VERSION 5.7 ;
  NOWIREEXTENSIONATPIN ON ;
  DIVIDERCHAR "/" ;
  BUSBITCHARS "[]" ;
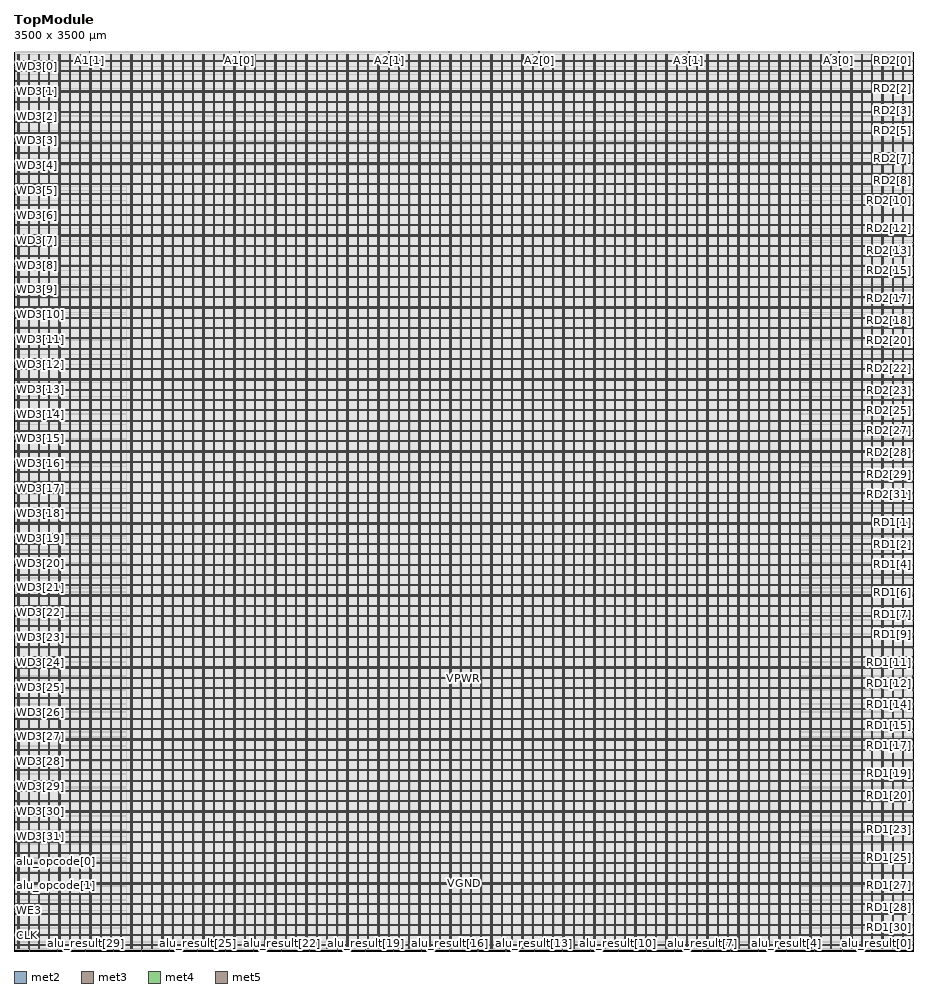
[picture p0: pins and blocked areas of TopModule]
MACRO TopModule
  CLASS BLOCK ;
  FOREIGN TopModule ;
  ORIGIN 0.000 0.000 ;
  SIZE 3500.000 BY 3500.000 ;
  PIN A1[0]
    DIRECTION INPUT ;
    USE SIGNAL ;
    ANTENNAGATEAREA 0.990000 ;
    PORT
      LAYER met2 ;
        RECT 875.010 3496.000 875.290 3500.000 ;
    END
  END A1[0]
  PIN A1[1]
    DIRECTION INPUT ;
    USE SIGNAL ;
    ANTENNAGATEAREA 0.990000 ;
    PORT
      LAYER met2 ;
        RECT 291.730 3496.000 292.010 3500.000 ;
    END
  END A1[1]
  PIN A2[0]
    DIRECTION INPUT ;
    USE SIGNAL ;
    ANTENNAGATEAREA 0.852000 ;
    PORT
      LAYER met2 ;
        RECT 2041.570 3496.000 2041.850 3500.000 ;
    END
  END A2[0]
  PIN A2[1]
    DIRECTION INPUT ;
    USE SIGNAL ;
    ANTENNAGATEAREA 0.495000 ;
    PORT
      LAYER met2 ;
        RECT 1458.290 3496.000 1458.570 3500.000 ;
    END
  END A2[1]
  PIN A3[0]
    DIRECTION INPUT ;
    USE SIGNAL ;
    ANTENNAGATEAREA 0.990000 ;
    PORT
      LAYER met2 ;
        RECT 3208.130 3496.000 3208.410 3500.000 ;
    END
  END A3[0]
  PIN A3[1]
    DIRECTION INPUT ;
    USE SIGNAL ;
    ANTENNAGATEAREA 0.990000 ;
    PORT
      LAYER met2 ;
        RECT 2624.850 3496.000 2625.130 3500.000 ;
    END
  END A3[1]
  PIN CLK
    DIRECTION INPUT ;
    USE SIGNAL ;
    ANTENNAGATEAREA 0.852000 ;
    ANTENNADIFFAREA 2.173500 ;
    PORT
      LAYER met3 ;
        RECT 0.000 59.880 4.000 60.480 ;
    END
  END CLK
  PIN RD1[0]
    DIRECTION OUTPUT ;
    USE SIGNAL ;
    ANTENNADIFFAREA 0.340600 ;
    PORT
      LAYER met3 ;
        RECT 3496.000 1721.800 3500.000 1722.400 ;
    END
  END RD1[0]
  PIN RD1[10]
    DIRECTION OUTPUT ;
    USE SIGNAL ;
    ANTENNADIFFAREA 0.340600 ;
    PORT
      LAYER met3 ;
        RECT 3496.000 1177.800 3500.000 1178.400 ;
    END
  END RD1[10]
  PIN RD1[11]
    DIRECTION OUTPUT ;
    USE SIGNAL ;
    ANTENNADIFFAREA 0.340600 ;
    PORT
      LAYER met3 ;
        RECT 3496.000 1123.400 3500.000 1124.000 ;
    END
  END RD1[11]
  PIN RD1[12]
    DIRECTION OUTPUT ;
    USE SIGNAL ;
    ANTENNADIFFAREA 0.340600 ;
    PORT
      LAYER met3 ;
        RECT 3496.000 1069.000 3500.000 1069.600 ;
    END
  END RD1[12]
  PIN RD1[13]
    DIRECTION OUTPUT ;
    USE SIGNAL ;
    ANTENNADIFFAREA 0.340600 ;
    PORT
      LAYER met3 ;
        RECT 3496.000 1014.600 3500.000 1015.200 ;
    END
  END RD1[13]
  PIN RD1[14]
    DIRECTION OUTPUT ;
    USE SIGNAL ;
    ANTENNADIFFAREA 0.340600 ;
    PORT
      LAYER met3 ;
        RECT 3496.000 960.200 3500.000 960.800 ;
    END
  END RD1[14]
  PIN RD1[15]
    DIRECTION OUTPUT ;
    USE SIGNAL ;
    ANTENNADIFFAREA 0.340600 ;
    PORT
      LAYER met3 ;
        RECT 3496.000 905.800 3500.000 906.400 ;
    END
  END RD1[15]
  PIN RD1[16]
    DIRECTION OUTPUT ;
    USE SIGNAL ;
    ANTENNADIFFAREA 0.340600 ;
    PORT
      LAYER met3 ;
        RECT 3496.000 851.400 3500.000 852.000 ;
    END
  END RD1[16]
  PIN RD1[17]
    DIRECTION OUTPUT ;
    USE SIGNAL ;
    ANTENNADIFFAREA 0.340600 ;
    PORT
      LAYER met3 ;
        RECT 3496.000 797.000 3500.000 797.600 ;
    END
  END RD1[17]
  PIN RD1[18]
    DIRECTION OUTPUT ;
    USE SIGNAL ;
    ANTENNADIFFAREA 0.340600 ;
    PORT
      LAYER met3 ;
        RECT 3496.000 742.600 3500.000 743.200 ;
    END
  END RD1[18]
  PIN RD1[19]
    DIRECTION OUTPUT ;
    USE SIGNAL ;
    ANTENNADIFFAREA 0.340600 ;
    PORT
      LAYER met3 ;
        RECT 3496.000 688.200 3500.000 688.800 ;
    END
  END RD1[19]
  PIN RD1[1]
    DIRECTION OUTPUT ;
    USE SIGNAL ;
    ANTENNADIFFAREA 0.340600 ;
    PORT
      LAYER met3 ;
        RECT 3496.000 1667.400 3500.000 1668.000 ;
    END
  END RD1[1]
  PIN RD1[20]
    DIRECTION OUTPUT ;
    USE SIGNAL ;
    ANTENNADIFFAREA 0.340600 ;
    PORT
      LAYER met3 ;
        RECT 3496.000 633.800 3500.000 634.400 ;
    END
  END RD1[20]
  PIN RD1[21]
    DIRECTION OUTPUT ;
    USE SIGNAL ;
    ANTENNADIFFAREA 0.340600 ;
    PORT
      LAYER met3 ;
        RECT 3496.000 579.400 3500.000 580.000 ;
    END
  END RD1[21]
  PIN RD1[22]
    DIRECTION OUTPUT ;
    USE SIGNAL ;
    ANTENNADIFFAREA 0.340600 ;
    PORT
      LAYER met3 ;
        RECT 3496.000 525.000 3500.000 525.600 ;
    END
  END RD1[22]
  PIN RD1[23]
    DIRECTION OUTPUT ;
    USE SIGNAL ;
    ANTENNADIFFAREA 0.340600 ;
    PORT
      LAYER met3 ;
        RECT 3496.000 470.600 3500.000 471.200 ;
    END
  END RD1[23]
  PIN RD1[24]
    DIRECTION OUTPUT ;
    USE SIGNAL ;
    ANTENNADIFFAREA 0.340600 ;
    PORT
      LAYER met3 ;
        RECT 3496.000 416.200 3500.000 416.800 ;
    END
  END RD1[24]
  PIN RD1[25]
    DIRECTION OUTPUT ;
    USE SIGNAL ;
    ANTENNADIFFAREA 0.340600 ;
    PORT
      LAYER met3 ;
        RECT 3496.000 361.800 3500.000 362.400 ;
    END
  END RD1[25]
  PIN RD1[26]
    DIRECTION OUTPUT ;
    USE SIGNAL ;
    ANTENNADIFFAREA 0.340600 ;
    PORT
      LAYER met3 ;
        RECT 3496.000 307.400 3500.000 308.000 ;
    END
  END RD1[26]
  PIN RD1[27]
    DIRECTION OUTPUT ;
    USE SIGNAL ;
    ANTENNADIFFAREA 0.340600 ;
    PORT
      LAYER met3 ;
        RECT 3496.000 253.000 3500.000 253.600 ;
    END
  END RD1[27]
  PIN RD1[28]
    DIRECTION OUTPUT ;
    USE SIGNAL ;
    ANTENNADIFFAREA 0.340600 ;
    PORT
      LAYER met3 ;
        RECT 3496.000 198.600 3500.000 199.200 ;
    END
  END RD1[28]
  PIN RD1[29]
    DIRECTION OUTPUT ;
    USE SIGNAL ;
    ANTENNADIFFAREA 0.340600 ;
    PORT
      LAYER met3 ;
        RECT 3496.000 144.200 3500.000 144.800 ;
    END
  END RD1[29]
  PIN RD1[2]
    DIRECTION OUTPUT ;
    USE SIGNAL ;
    ANTENNADIFFAREA 0.340600 ;
    PORT
      LAYER met3 ;
        RECT 3496.000 1613.000 3500.000 1613.600 ;
    END
  END RD1[2]
  PIN RD1[30]
    DIRECTION OUTPUT ;
    USE SIGNAL ;
    ANTENNADIFFAREA 0.340600 ;
    PORT
      LAYER met3 ;
        RECT 3496.000 89.800 3500.000 90.400 ;
    END
  END RD1[30]
  PIN RD1[31]
    DIRECTION OUTPUT ;
    USE SIGNAL ;
    ANTENNADIFFAREA 0.340600 ;
    PORT
      LAYER met3 ;
        RECT 3496.000 35.400 3500.000 36.000 ;
    END
  END RD1[31]
  PIN RD1[3]
    DIRECTION OUTPUT ;
    USE SIGNAL ;
    ANTENNADIFFAREA 0.340600 ;
    PORT
      LAYER met3 ;
        RECT 3496.000 1558.600 3500.000 1559.200 ;
    END
  END RD1[3]
  PIN RD1[4]
    DIRECTION OUTPUT ;
    USE SIGNAL ;
    ANTENNADIFFAREA 0.340600 ;
    PORT
      LAYER met3 ;
        RECT 3496.000 1504.200 3500.000 1504.800 ;
    END
  END RD1[4]
  PIN RD1[5]
    DIRECTION OUTPUT ;
    USE SIGNAL ;
    ANTENNADIFFAREA 0.340600 ;
    PORT
      LAYER met3 ;
        RECT 3496.000 1449.800 3500.000 1450.400 ;
    END
  END RD1[5]
  PIN RD1[6]
    DIRECTION OUTPUT ;
    USE SIGNAL ;
    ANTENNADIFFAREA 0.340600 ;
    PORT
      LAYER met3 ;
        RECT 3496.000 1395.400 3500.000 1396.000 ;
    END
  END RD1[6]
  PIN RD1[7]
    DIRECTION OUTPUT ;
    USE SIGNAL ;
    ANTENNADIFFAREA 0.340600 ;
    PORT
      LAYER met3 ;
        RECT 3496.000 1341.000 3500.000 1341.600 ;
    END
  END RD1[7]
  PIN RD1[8]
    DIRECTION OUTPUT ;
    USE SIGNAL ;
    ANTENNADIFFAREA 0.340600 ;
    PORT
      LAYER met3 ;
        RECT 3496.000 1286.600 3500.000 1287.200 ;
    END
  END RD1[8]
  PIN RD1[9]
    DIRECTION OUTPUT ;
    USE SIGNAL ;
    ANTENNADIFFAREA 0.340600 ;
    PORT
      LAYER met3 ;
        RECT 3496.000 1232.200 3500.000 1232.800 ;
    END
  END RD1[9]
  PIN RD2[0]
    DIRECTION OUTPUT ;
    USE SIGNAL ;
    ANTENNADIFFAREA 0.340600 ;
    PORT
      LAYER met3 ;
        RECT 3496.000 3462.600 3500.000 3463.200 ;
    END
  END RD2[0]
  PIN RD2[10]
    DIRECTION OUTPUT ;
    USE SIGNAL ;
    ANTENNADIFFAREA 0.340600 ;
    PORT
      LAYER met3 ;
        RECT 3496.000 2918.600 3500.000 2919.200 ;
    END
  END RD2[10]
  PIN RD2[11]
    DIRECTION OUTPUT ;
    USE SIGNAL ;
    ANTENNADIFFAREA 0.340600 ;
    PORT
      LAYER met3 ;
        RECT 3496.000 2864.200 3500.000 2864.800 ;
    END
  END RD2[11]
  PIN RD2[12]
    DIRECTION OUTPUT ;
    USE SIGNAL ;
    ANTENNADIFFAREA 0.340600 ;
    PORT
      LAYER met3 ;
        RECT 3496.000 2809.800 3500.000 2810.400 ;
    END
  END RD2[12]
  PIN RD2[13]
    DIRECTION OUTPUT ;
    USE SIGNAL ;
    ANTENNADIFFAREA 0.340600 ;
    PORT
      LAYER met3 ;
        RECT 3496.000 2755.400 3500.000 2756.000 ;
    END
  END RD2[13]
  PIN RD2[14]
    DIRECTION OUTPUT ;
    USE SIGNAL ;
    ANTENNADIFFAREA 0.340600 ;
    PORT
      LAYER met3 ;
        RECT 3496.000 2701.000 3500.000 2701.600 ;
    END
  END RD2[14]
  PIN RD2[15]
    DIRECTION OUTPUT ;
    USE SIGNAL ;
    ANTENNADIFFAREA 0.340600 ;
    PORT
      LAYER met3 ;
        RECT 3496.000 2646.600 3500.000 2647.200 ;
    END
  END RD2[15]
  PIN RD2[16]
    DIRECTION OUTPUT ;
    USE SIGNAL ;
    ANTENNADIFFAREA 0.340600 ;
    PORT
      LAYER met3 ;
        RECT 3496.000 2592.200 3500.000 2592.800 ;
    END
  END RD2[16]
  PIN RD2[17]
    DIRECTION OUTPUT ;
    USE SIGNAL ;
    ANTENNADIFFAREA 0.340600 ;
    PORT
      LAYER met3 ;
        RECT 3496.000 2537.800 3500.000 2538.400 ;
    END
  END RD2[17]
  PIN RD2[18]
    DIRECTION OUTPUT ;
    USE SIGNAL ;
    ANTENNADIFFAREA 0.340600 ;
    PORT
      LAYER met3 ;
        RECT 3496.000 2483.400 3500.000 2484.000 ;
    END
  END RD2[18]
  PIN RD2[19]
    DIRECTION OUTPUT ;
    USE SIGNAL ;
    ANTENNADIFFAREA 0.340600 ;
    PORT
      LAYER met3 ;
        RECT 3496.000 2429.000 3500.000 2429.600 ;
    END
  END RD2[19]
  PIN RD2[1]
    DIRECTION OUTPUT ;
    USE SIGNAL ;
    ANTENNADIFFAREA 0.340600 ;
    PORT
      LAYER met3 ;
        RECT 3496.000 3408.200 3500.000 3408.800 ;
    END
  END RD2[1]
  PIN RD2[20]
    DIRECTION OUTPUT ;
    USE SIGNAL ;
    ANTENNADIFFAREA 0.340600 ;
    PORT
      LAYER met3 ;
        RECT 3496.000 2374.600 3500.000 2375.200 ;
    END
  END RD2[20]
  PIN RD2[21]
    DIRECTION OUTPUT ;
    USE SIGNAL ;
    ANTENNADIFFAREA 0.340600 ;
    PORT
      LAYER met3 ;
        RECT 3496.000 2320.200 3500.000 2320.800 ;
    END
  END RD2[21]
  PIN RD2[22]
    DIRECTION OUTPUT ;
    USE SIGNAL ;
    ANTENNADIFFAREA 0.340600 ;
    PORT
      LAYER met3 ;
        RECT 3496.000 2265.800 3500.000 2266.400 ;
    END
  END RD2[22]
  PIN RD2[23]
    DIRECTION OUTPUT ;
    USE SIGNAL ;
    ANTENNADIFFAREA 0.340600 ;
    PORT
      LAYER met3 ;
        RECT 3496.000 2211.400 3500.000 2212.000 ;
    END
  END RD2[23]
  PIN RD2[24]
    DIRECTION OUTPUT ;
    USE SIGNAL ;
    ANTENNADIFFAREA 0.340600 ;
    PORT
      LAYER met3 ;
        RECT 3496.000 2157.000 3500.000 2157.600 ;
    END
  END RD2[24]
  PIN RD2[25]
    DIRECTION OUTPUT ;
    USE SIGNAL ;
    ANTENNADIFFAREA 0.340600 ;
    PORT
      LAYER met3 ;
        RECT 3496.000 2102.600 3500.000 2103.200 ;
    END
  END RD2[25]
  PIN RD2[26]
    DIRECTION OUTPUT ;
    USE SIGNAL ;
    ANTENNADIFFAREA 0.340600 ;
    PORT
      LAYER met3 ;
        RECT 3496.000 2048.200 3500.000 2048.800 ;
    END
  END RD2[26]
  PIN RD2[27]
    DIRECTION OUTPUT ;
    USE SIGNAL ;
    ANTENNADIFFAREA 0.340600 ;
    PORT
      LAYER met3 ;
        RECT 3496.000 1993.800 3500.000 1994.400 ;
    END
  END RD2[27]
  PIN RD2[28]
    DIRECTION OUTPUT ;
    USE SIGNAL ;
    ANTENNADIFFAREA 0.340600 ;
    PORT
      LAYER met3 ;
        RECT 3496.000 1939.400 3500.000 1940.000 ;
    END
  END RD2[28]
  PIN RD2[29]
    DIRECTION OUTPUT ;
    USE SIGNAL ;
    ANTENNADIFFAREA 0.340600 ;
    PORT
      LAYER met3 ;
        RECT 3496.000 1885.000 3500.000 1885.600 ;
    END
  END RD2[29]
  PIN RD2[2]
    DIRECTION OUTPUT ;
    USE SIGNAL ;
    ANTENNADIFFAREA 0.340600 ;
    PORT
      LAYER met3 ;
        RECT 3496.000 3353.800 3500.000 3354.400 ;
    END
  END RD2[2]
  PIN RD2[30]
    DIRECTION OUTPUT ;
    USE SIGNAL ;
    ANTENNADIFFAREA 0.340600 ;
    PORT
      LAYER met3 ;
        RECT 3496.000 1830.600 3500.000 1831.200 ;
    END
  END RD2[30]
  PIN RD2[31]
    DIRECTION OUTPUT ;
    USE SIGNAL ;
    ANTENNADIFFAREA 0.340600 ;
    PORT
      LAYER met3 ;
        RECT 3496.000 1776.200 3500.000 1776.800 ;
    END
  END RD2[31]
  PIN RD2[3]
    DIRECTION OUTPUT ;
    USE SIGNAL ;
    ANTENNADIFFAREA 0.340600 ;
    PORT
      LAYER met3 ;
        RECT 3496.000 3299.400 3500.000 3300.000 ;
    END
  END RD2[3]
  PIN RD2[4]
    DIRECTION OUTPUT ;
    USE SIGNAL ;
    ANTENNADIFFAREA 0.340600 ;
    PORT
      LAYER met3 ;
        RECT 3496.000 3245.000 3500.000 3245.600 ;
    END
  END RD2[4]
  PIN RD2[5]
    DIRECTION OUTPUT ;
    USE SIGNAL ;
    ANTENNADIFFAREA 0.340600 ;
    PORT
      LAYER met3 ;
        RECT 3496.000 3190.600 3500.000 3191.200 ;
    END
  END RD2[5]
  PIN RD2[6]
    DIRECTION OUTPUT ;
    USE SIGNAL ;
    ANTENNADIFFAREA 0.340600 ;
    PORT
      LAYER met3 ;
        RECT 3496.000 3136.200 3500.000 3136.800 ;
    END
  END RD2[6]
  PIN RD2[7]
    DIRECTION OUTPUT ;
    USE SIGNAL ;
    ANTENNADIFFAREA 0.340600 ;
    PORT
      LAYER met3 ;
        RECT 3496.000 3081.800 3500.000 3082.400 ;
    END
  END RD2[7]
  PIN RD2[8]
    DIRECTION OUTPUT ;
    USE SIGNAL ;
    ANTENNADIFFAREA 0.340600 ;
    PORT
      LAYER met3 ;
        RECT 3496.000 3027.400 3500.000 3028.000 ;
    END
  END RD2[8]
  PIN RD2[9]
    DIRECTION OUTPUT ;
    USE SIGNAL ;
    ANTENNADIFFAREA 0.340600 ;
    PORT
      LAYER met3 ;
        RECT 3496.000 2973.000 3500.000 2973.600 ;
    END
  END RD2[9]
  PIN VGND
    DIRECTION INOUT ;
    USE GROUND ;
    PORT
      LAYER met4 ;
        RECT 18.020 10.640 19.620 3487.280 ;
    END
    PORT
      LAYER met4 ;
        RECT 58.020 10.640 59.620 3487.280 ;
    END
    PORT
      LAYER met4 ;
        RECT 98.020 10.640 99.620 3487.280 ;
    END
    PORT
      LAYER met4 ;
        RECT 138.020 10.640 139.620 3487.280 ;
    END
    PORT
      LAYER met4 ;
        RECT 178.020 10.640 179.620 3487.280 ;
    END
    PORT
      LAYER met4 ;
        RECT 218.020 10.640 219.620 3487.280 ;
    END
    PORT
      LAYER met4 ;
        RECT 258.020 10.640 259.620 3487.280 ;
    END
    PORT
      LAYER met4 ;
        RECT 298.020 10.640 299.620 3487.280 ;
    END
    PORT
      LAYER met4 ;
        RECT 338.020 10.640 339.620 3487.280 ;
    END
    PORT
      LAYER met4 ;
        RECT 378.020 10.640 379.620 3487.280 ;
    END
    PORT
      LAYER met4 ;
        RECT 418.020 10.640 419.620 3487.280 ;
    END
    PORT
      LAYER met4 ;
        RECT 458.020 10.640 459.620 3487.280 ;
    END
    PORT
      LAYER met4 ;
        RECT 498.020 10.640 499.620 3487.280 ;
    END
    PORT
      LAYER met4 ;
        RECT 538.020 10.640 539.620 3487.280 ;
    END
    PORT
      LAYER met4 ;
        RECT 578.020 10.640 579.620 3487.280 ;
    END
    PORT
      LAYER met4 ;
        RECT 618.020 10.640 619.620 3487.280 ;
    END
    PORT
      LAYER met4 ;
        RECT 658.020 10.640 659.620 3487.280 ;
    END
    PORT
      LAYER met4 ;
        RECT 698.020 10.640 699.620 3487.280 ;
    END
    PORT
      LAYER met4 ;
        RECT 738.020 10.640 739.620 3487.280 ;
    END
    PORT
      LAYER met4 ;
        RECT 778.020 10.640 779.620 3487.280 ;
    END
    PORT
      LAYER met4 ;
        RECT 818.020 10.640 819.620 3487.280 ;
    END
    PORT
      LAYER met4 ;
        RECT 858.020 10.640 859.620 3487.280 ;
    END
    PORT
      LAYER met4 ;
        RECT 898.020 10.640 899.620 3487.280 ;
    END
    PORT
      LAYER met4 ;
        RECT 938.020 10.640 939.620 3487.280 ;
    END
    PORT
      LAYER met4 ;
        RECT 978.020 10.640 979.620 3487.280 ;
    END
    PORT
      LAYER met4 ;
        RECT 1018.020 10.640 1019.620 3487.280 ;
    END
    PORT
      LAYER met4 ;
        RECT 1058.020 10.640 1059.620 3487.280 ;
    END
    PORT
      LAYER met4 ;
        RECT 1098.020 10.640 1099.620 3487.280 ;
    END
    PORT
      LAYER met4 ;
        RECT 1138.020 10.640 1139.620 3487.280 ;
    END
    PORT
      LAYER met4 ;
        RECT 1178.020 10.640 1179.620 3487.280 ;
    END
    PORT
      LAYER met4 ;
        RECT 1218.020 10.640 1219.620 3487.280 ;
    END
    PORT
      LAYER met4 ;
        RECT 1258.020 10.640 1259.620 3487.280 ;
    END
    PORT
      LAYER met4 ;
        RECT 1298.020 10.640 1299.620 3487.280 ;
    END
    PORT
      LAYER met4 ;
        RECT 1338.020 10.640 1339.620 3487.280 ;
    END
    PORT
      LAYER met4 ;
        RECT 1378.020 10.640 1379.620 3487.280 ;
    END
    PORT
      LAYER met4 ;
        RECT 1418.020 10.640 1419.620 3487.280 ;
    END
    PORT
      LAYER met4 ;
        RECT 1458.020 10.640 1459.620 3487.280 ;
    END
    PORT
      LAYER met4 ;
        RECT 1498.020 10.640 1499.620 3487.280 ;
    END
    PORT
      LAYER met4 ;
        RECT 1538.020 10.640 1539.620 3487.280 ;
    END
    PORT
      LAYER met4 ;
        RECT 1578.020 10.640 1579.620 3487.280 ;
    END
    PORT
      LAYER met4 ;
        RECT 1618.020 10.640 1619.620 3487.280 ;
    END
    PORT
      LAYER met4 ;
        RECT 1658.020 10.640 1659.620 3487.280 ;
    END
    PORT
      LAYER met4 ;
        RECT 1698.020 10.640 1699.620 3487.280 ;
    END
    PORT
      LAYER met4 ;
        RECT 1738.020 10.640 1739.620 3487.280 ;
    END
    PORT
      LAYER met4 ;
        RECT 1778.020 10.640 1779.620 3487.280 ;
    END
    PORT
      LAYER met4 ;
        RECT 1818.020 10.640 1819.620 3487.280 ;
    END
    PORT
      LAYER met4 ;
        RECT 1858.020 10.640 1859.620 3487.280 ;
    END
    PORT
      LAYER met4 ;
        RECT 1898.020 10.640 1899.620 3487.280 ;
    END
    PORT
      LAYER met4 ;
        RECT 1938.020 10.640 1939.620 3487.280 ;
    END
    PORT
      LAYER met4 ;
        RECT 1978.020 10.640 1979.620 3487.280 ;
    END
    PORT
      LAYER met4 ;
        RECT 2018.020 10.640 2019.620 3487.280 ;
    END
    PORT
      LAYER met4 ;
        RECT 2058.020 10.640 2059.620 3487.280 ;
    END
    PORT
      LAYER met4 ;
        RECT 2098.020 10.640 2099.620 3487.280 ;
    END
    PORT
      LAYER met4 ;
        RECT 2138.020 10.640 2139.620 3487.280 ;
    END
    PORT
      LAYER met4 ;
        RECT 2178.020 10.640 2179.620 3487.280 ;
    END
    PORT
      LAYER met4 ;
        RECT 2218.020 10.640 2219.620 3487.280 ;
    END
    PORT
      LAYER met4 ;
        RECT 2258.020 10.640 2259.620 3487.280 ;
    END
    PORT
      LAYER met4 ;
        RECT 2298.020 10.640 2299.620 3487.280 ;
    END
    PORT
      LAYER met4 ;
        RECT 2338.020 10.640 2339.620 3487.280 ;
    END
    PORT
      LAYER met4 ;
        RECT 2378.020 10.640 2379.620 3487.280 ;
    END
    PORT
      LAYER met4 ;
        RECT 2418.020 10.640 2419.620 3487.280 ;
    END
    PORT
      LAYER met4 ;
        RECT 2458.020 10.640 2459.620 3487.280 ;
    END
    PORT
      LAYER met4 ;
        RECT 2498.020 10.640 2499.620 3487.280 ;
    END
    PORT
      LAYER met4 ;
        RECT 2538.020 10.640 2539.620 3487.280 ;
    END
    PORT
      LAYER met4 ;
        RECT 2578.020 10.640 2579.620 3487.280 ;
    END
    PORT
      LAYER met4 ;
        RECT 2618.020 10.640 2619.620 3487.280 ;
    END
    PORT
      LAYER met4 ;
        RECT 2658.020 10.640 2659.620 3487.280 ;
    END
    PORT
      LAYER met4 ;
        RECT 2698.020 10.640 2699.620 3487.280 ;
    END
    PORT
      LAYER met4 ;
        RECT 2738.020 10.640 2739.620 3487.280 ;
    END
    PORT
      LAYER met4 ;
        RECT 2778.020 10.640 2779.620 3487.280 ;
    END
    PORT
      LAYER met4 ;
        RECT 2818.020 10.640 2819.620 3487.280 ;
    END
    PORT
      LAYER met4 ;
        RECT 2858.020 10.640 2859.620 3487.280 ;
    END
    PORT
      LAYER met4 ;
        RECT 2898.020 10.640 2899.620 3487.280 ;
    END
    PORT
      LAYER met4 ;
        RECT 2938.020 10.640 2939.620 3487.280 ;
    END
    PORT
      LAYER met4 ;
        RECT 2978.020 10.640 2979.620 3487.280 ;
    END
    PORT
      LAYER met4 ;
        RECT 3018.020 10.640 3019.620 3487.280 ;
    END
    PORT
      LAYER met4 ;
        RECT 3058.020 10.640 3059.620 3487.280 ;
    END
    PORT
      LAYER met4 ;
        RECT 3098.020 10.640 3099.620 3487.280 ;
    END
    PORT
      LAYER met4 ;
        RECT 3138.020 10.640 3139.620 3487.280 ;
    END
    PORT
      LAYER met4 ;
        RECT 3178.020 10.640 3179.620 3487.280 ;
    END
    PORT
      LAYER met4 ;
        RECT 3218.020 10.640 3219.620 3487.280 ;
    END
    PORT
      LAYER met4 ;
        RECT 3258.020 10.640 3259.620 3487.280 ;
    END
    PORT
      LAYER met4 ;
        RECT 3298.020 10.640 3299.620 3487.280 ;
    END
    PORT
      LAYER met4 ;
        RECT 3338.020 10.640 3339.620 3487.280 ;
    END
    PORT
      LAYER met4 ;
        RECT 3378.020 10.640 3379.620 3487.280 ;
    END
    PORT
      LAYER met4 ;
        RECT 3418.020 10.640 3419.620 3487.280 ;
    END
    PORT
      LAYER met4 ;
        RECT 3458.020 10.640 3459.620 3487.280 ;
    END
    PORT
      LAYER met5 ;
        RECT 5.280 23.380 3494.400 24.980 ;
    END
    PORT
      LAYER met5 ;
        RECT 5.280 63.380 3494.400 64.980 ;
    END
    PORT
      LAYER met5 ;
        RECT 5.280 103.380 3494.400 104.980 ;
    END
    PORT
      LAYER met5 ;
        RECT 5.280 143.380 3494.400 144.980 ;
    END
    PORT
      LAYER met5 ;
        RECT 5.280 183.380 3494.400 184.980 ;
    END
    PORT
      LAYER met5 ;
        RECT 5.280 223.380 3494.400 224.980 ;
    END
    PORT
      LAYER met5 ;
        RECT 5.280 263.380 3494.400 264.980 ;
    END
    PORT
      LAYER met5 ;
        RECT 5.280 303.380 3494.400 304.980 ;
    END
    PORT
      LAYER met5 ;
        RECT 5.280 343.380 3494.400 344.980 ;
    END
    PORT
      LAYER met5 ;
        RECT 5.280 383.380 3494.400 384.980 ;
    END
    PORT
      LAYER met5 ;
        RECT 5.280 423.380 3494.400 424.980 ;
    END
    PORT
      LAYER met5 ;
        RECT 5.280 463.380 3494.400 464.980 ;
    END
    PORT
      LAYER met5 ;
        RECT 5.280 503.380 3494.400 504.980 ;
    END
    PORT
      LAYER met5 ;
        RECT 5.280 543.380 3494.400 544.980 ;
    END
    PORT
      LAYER met5 ;
        RECT 5.280 583.380 3494.400 584.980 ;
    END
    PORT
      LAYER met5 ;
        RECT 5.280 623.380 3494.400 624.980 ;
    END
    PORT
      LAYER met5 ;
        RECT 5.280 663.380 3494.400 664.980 ;
    END
    PORT
      LAYER met5 ;
        RECT 5.280 703.380 3494.400 704.980 ;
    END
    PORT
      LAYER met5 ;
        RECT 5.280 743.380 3494.400 744.980 ;
    END
    PORT
      LAYER met5 ;
        RECT 5.280 783.380 3494.400 784.980 ;
    END
    PORT
      LAYER met5 ;
        RECT 5.280 823.380 3494.400 824.980 ;
    END
    PORT
      LAYER met5 ;
        RECT 5.280 863.380 3494.400 864.980 ;
    END
    PORT
      LAYER met5 ;
        RECT 5.280 903.380 3494.400 904.980 ;
    END
    PORT
      LAYER met5 ;
        RECT 5.280 943.380 3494.400 944.980 ;
    END
    PORT
      LAYER met5 ;
        RECT 5.280 983.380 3494.400 984.980 ;
    END
    PORT
      LAYER met5 ;
        RECT 5.280 1023.380 3494.400 1024.980 ;
    END
    PORT
      LAYER met5 ;
        RECT 5.280 1063.380 3494.400 1064.980 ;
    END
    PORT
      LAYER met5 ;
        RECT 5.280 1103.380 3494.400 1104.980 ;
    END
    PORT
      LAYER met5 ;
        RECT 5.280 1143.380 3494.400 1144.980 ;
    END
    PORT
      LAYER met5 ;
        RECT 5.280 1183.380 3494.400 1184.980 ;
    END
    PORT
      LAYER met5 ;
        RECT 5.280 1223.380 3494.400 1224.980 ;
    END
    PORT
      LAYER met5 ;
        RECT 5.280 1263.380 3494.400 1264.980 ;
    END
    PORT
      LAYER met5 ;
        RECT 5.280 1303.380 3494.400 1304.980 ;
    END
    PORT
      LAYER met5 ;
        RECT 5.280 1343.380 3494.400 1344.980 ;
    END
    PORT
      LAYER met5 ;
        RECT 5.280 1383.380 3494.400 1384.980 ;
    END
    PORT
      LAYER met5 ;
        RECT 5.280 1423.380 3494.400 1424.980 ;
    END
    PORT
      LAYER met5 ;
        RECT 5.280 1463.380 3494.400 1464.980 ;
    END
    PORT
      LAYER met5 ;
        RECT 5.280 1503.380 3494.400 1504.980 ;
    END
    PORT
      LAYER met5 ;
        RECT 5.280 1543.380 3494.400 1544.980 ;
    END
    PORT
      LAYER met5 ;
        RECT 5.280 1583.380 3494.400 1584.980 ;
    END
    PORT
      LAYER met5 ;
        RECT 5.280 1623.380 3494.400 1624.980 ;
    END
    PORT
      LAYER met5 ;
        RECT 5.280 1663.380 3494.400 1664.980 ;
    END
    PORT
      LAYER met5 ;
        RECT 5.280 1703.380 3494.400 1704.980 ;
    END
    PORT
      LAYER met5 ;
        RECT 5.280 1743.380 3494.400 1744.980 ;
    END
    PORT
      LAYER met5 ;
        RECT 5.280 1783.380 3494.400 1784.980 ;
    END
    PORT
      LAYER met5 ;
        RECT 5.280 1823.380 3494.400 1824.980 ;
    END
    PORT
      LAYER met5 ;
        RECT 5.280 1863.380 3494.400 1864.980 ;
    END
    PORT
      LAYER met5 ;
        RECT 5.280 1903.380 3494.400 1904.980 ;
    END
    PORT
      LAYER met5 ;
        RECT 5.280 1943.380 3494.400 1944.980 ;
    END
    PORT
      LAYER met5 ;
        RECT 5.280 1983.380 3494.400 1984.980 ;
    END
    PORT
      LAYER met5 ;
        RECT 5.280 2023.380 3494.400 2024.980 ;
    END
    PORT
      LAYER met5 ;
        RECT 5.280 2063.380 3494.400 2064.980 ;
    END
    PORT
      LAYER met5 ;
        RECT 5.280 2103.380 3494.400 2104.980 ;
    END
    PORT
      LAYER met5 ;
        RECT 5.280 2143.380 3494.400 2144.980 ;
    END
    PORT
      LAYER met5 ;
        RECT 5.280 2183.380 3494.400 2184.980 ;
    END
    PORT
      LAYER met5 ;
        RECT 5.280 2223.380 3494.400 2224.980 ;
    END
    PORT
      LAYER met5 ;
        RECT 5.280 2263.380 3494.400 2264.980 ;
    END
    PORT
      LAYER met5 ;
        RECT 5.280 2303.380 3494.400 2304.980 ;
    END
    PORT
      LAYER met5 ;
        RECT 5.280 2343.380 3494.400 2344.980 ;
    END
    PORT
      LAYER met5 ;
        RECT 5.280 2383.380 3494.400 2384.980 ;
    END
    PORT
      LAYER met5 ;
        RECT 5.280 2423.380 3494.400 2424.980 ;
    END
    PORT
      LAYER met5 ;
        RECT 5.280 2463.380 3494.400 2464.980 ;
    END
    PORT
      LAYER met5 ;
        RECT 5.280 2503.380 3494.400 2504.980 ;
    END
    PORT
      LAYER met5 ;
        RECT 5.280 2543.380 3494.400 2544.980 ;
    END
    PORT
      LAYER met5 ;
        RECT 5.280 2583.380 3494.400 2584.980 ;
    END
    PORT
      LAYER met5 ;
        RECT 5.280 2623.380 3494.400 2624.980 ;
    END
    PORT
      LAYER met5 ;
        RECT 5.280 2663.380 3494.400 2664.980 ;
    END
    PORT
      LAYER met5 ;
        RECT 5.280 2703.380 3494.400 2704.980 ;
    END
    PORT
      LAYER met5 ;
        RECT 5.280 2743.380 3494.400 2744.980 ;
    END
    PORT
      LAYER met5 ;
        RECT 5.280 2783.380 3494.400 2784.980 ;
    END
    PORT
      LAYER met5 ;
        RECT 5.280 2823.380 3494.400 2824.980 ;
    END
    PORT
      LAYER met5 ;
        RECT 5.280 2863.380 3494.400 2864.980 ;
    END
    PORT
      LAYER met5 ;
        RECT 5.280 2903.380 3494.400 2904.980 ;
    END
    PORT
      LAYER met5 ;
        RECT 5.280 2943.380 3494.400 2944.980 ;
    END
    PORT
      LAYER met5 ;
        RECT 5.280 2983.380 3494.400 2984.980 ;
    END
    PORT
      LAYER met5 ;
        RECT 5.280 3023.380 3494.400 3024.980 ;
    END
    PORT
      LAYER met5 ;
        RECT 5.280 3063.380 3494.400 3064.980 ;
    END
    PORT
      LAYER met5 ;
        RECT 5.280 3103.380 3494.400 3104.980 ;
    END
    PORT
      LAYER met5 ;
        RECT 5.280 3143.380 3494.400 3144.980 ;
    END
    PORT
      LAYER met5 ;
        RECT 5.280 3183.380 3494.400 3184.980 ;
    END
    PORT
      LAYER met5 ;
        RECT 5.280 3223.380 3494.400 3224.980 ;
    END
    PORT
      LAYER met5 ;
        RECT 5.280 3263.380 3494.400 3264.980 ;
    END
    PORT
      LAYER met5 ;
        RECT 5.280 3303.380 3494.400 3304.980 ;
    END
    PORT
      LAYER met5 ;
        RECT 5.280 3343.380 3494.400 3344.980 ;
    END
    PORT
      LAYER met5 ;
        RECT 5.280 3383.380 3494.400 3384.980 ;
    END
    PORT
      LAYER met5 ;
        RECT 5.280 3423.380 3494.400 3424.980 ;
    END
    PORT
      LAYER met5 ;
        RECT 5.280 3463.380 3494.400 3464.980 ;
    END
  END VGND
  PIN VPWR
    DIRECTION INOUT ;
    USE POWER ;
    PORT
      LAYER met4 ;
        RECT 14.720 10.640 16.320 3487.280 ;
    END
    PORT
      LAYER met4 ;
        RECT 54.720 10.640 56.320 3487.280 ;
    END
    PORT
      LAYER met4 ;
        RECT 94.720 10.640 96.320 3487.280 ;
    END
    PORT
      LAYER met4 ;
        RECT 134.720 10.640 136.320 3487.280 ;
    END
    PORT
      LAYER met4 ;
        RECT 174.720 10.640 176.320 3487.280 ;
    END
    PORT
      LAYER met4 ;
        RECT 214.720 10.640 216.320 3487.280 ;
    END
    PORT
      LAYER met4 ;
        RECT 254.720 10.640 256.320 3487.280 ;
    END
    PORT
      LAYER met4 ;
        RECT 294.720 10.640 296.320 3487.280 ;
    END
    PORT
      LAYER met4 ;
        RECT 334.720 10.640 336.320 3487.280 ;
    END
    PORT
      LAYER met4 ;
        RECT 374.720 10.640 376.320 3487.280 ;
    END
    PORT
      LAYER met4 ;
        RECT 414.720 10.640 416.320 3487.280 ;
    END
    PORT
      LAYER met4 ;
        RECT 454.720 10.640 456.320 3487.280 ;
    END
    PORT
      LAYER met4 ;
        RECT 494.720 10.640 496.320 3487.280 ;
    END
    PORT
      LAYER met4 ;
        RECT 534.720 10.640 536.320 3487.280 ;
    END
    PORT
      LAYER met4 ;
        RECT 574.720 10.640 576.320 3487.280 ;
    END
    PORT
      LAYER met4 ;
        RECT 614.720 10.640 616.320 3487.280 ;
    END
    PORT
      LAYER met4 ;
        RECT 654.720 10.640 656.320 3487.280 ;
    END
    PORT
      LAYER met4 ;
        RECT 694.720 10.640 696.320 3487.280 ;
    END
    PORT
      LAYER met4 ;
        RECT 734.720 10.640 736.320 3487.280 ;
    END
    PORT
      LAYER met4 ;
        RECT 774.720 10.640 776.320 3487.280 ;
    END
    PORT
      LAYER met4 ;
        RECT 814.720 10.640 816.320 3487.280 ;
    END
    PORT
      LAYER met4 ;
        RECT 854.720 10.640 856.320 3487.280 ;
    END
    PORT
      LAYER met4 ;
        RECT 894.720 10.640 896.320 3487.280 ;
    END
    PORT
      LAYER met4 ;
        RECT 934.720 10.640 936.320 3487.280 ;
    END
    PORT
      LAYER met4 ;
        RECT 974.720 10.640 976.320 3487.280 ;
    END
    PORT
      LAYER met4 ;
        RECT 1014.720 10.640 1016.320 3487.280 ;
    END
    PORT
      LAYER met4 ;
        RECT 1054.720 10.640 1056.320 3487.280 ;
    END
    PORT
      LAYER met4 ;
        RECT 1094.720 10.640 1096.320 3487.280 ;
    END
    PORT
      LAYER met4 ;
        RECT 1134.720 10.640 1136.320 3487.280 ;
    END
    PORT
      LAYER met4 ;
        RECT 1174.720 10.640 1176.320 3487.280 ;
    END
    PORT
      LAYER met4 ;
        RECT 1214.720 10.640 1216.320 3487.280 ;
    END
    PORT
      LAYER met4 ;
        RECT 1254.720 10.640 1256.320 3487.280 ;
    END
    PORT
      LAYER met4 ;
        RECT 1294.720 10.640 1296.320 3487.280 ;
    END
    PORT
      LAYER met4 ;
        RECT 1334.720 10.640 1336.320 3487.280 ;
    END
    PORT
      LAYER met4 ;
        RECT 1374.720 10.640 1376.320 3487.280 ;
    END
    PORT
      LAYER met4 ;
        RECT 1414.720 10.640 1416.320 3487.280 ;
    END
    PORT
      LAYER met4 ;
        RECT 1454.720 10.640 1456.320 3487.280 ;
    END
    PORT
      LAYER met4 ;
        RECT 1494.720 10.640 1496.320 3487.280 ;
    END
    PORT
      LAYER met4 ;
        RECT 1534.720 10.640 1536.320 3487.280 ;
    END
    PORT
      LAYER met4 ;
        RECT 1574.720 10.640 1576.320 3487.280 ;
    END
    PORT
      LAYER met4 ;
        RECT 1614.720 10.640 1616.320 3487.280 ;
    END
    PORT
      LAYER met4 ;
        RECT 1654.720 10.640 1656.320 3487.280 ;
    END
    PORT
      LAYER met4 ;
        RECT 1694.720 10.640 1696.320 3487.280 ;
    END
    PORT
      LAYER met4 ;
        RECT 1734.720 10.640 1736.320 3487.280 ;
    END
    PORT
      LAYER met4 ;
        RECT 1774.720 10.640 1776.320 3487.280 ;
    END
    PORT
      LAYER met4 ;
        RECT 1814.720 10.640 1816.320 3487.280 ;
    END
    PORT
      LAYER met4 ;
        RECT 1854.720 10.640 1856.320 3487.280 ;
    END
    PORT
      LAYER met4 ;
        RECT 1894.720 10.640 1896.320 3487.280 ;
    END
    PORT
      LAYER met4 ;
        RECT 1934.720 10.640 1936.320 3487.280 ;
    END
    PORT
      LAYER met4 ;
        RECT 1974.720 10.640 1976.320 3487.280 ;
    END
    PORT
      LAYER met4 ;
        RECT 2014.720 10.640 2016.320 3487.280 ;
    END
    PORT
      LAYER met4 ;
        RECT 2054.720 10.640 2056.320 3487.280 ;
    END
    PORT
      LAYER met4 ;
        RECT 2094.720 10.640 2096.320 3487.280 ;
    END
    PORT
      LAYER met4 ;
        RECT 2134.720 10.640 2136.320 3487.280 ;
    END
    PORT
      LAYER met4 ;
        RECT 2174.720 10.640 2176.320 3487.280 ;
    END
    PORT
      LAYER met4 ;
        RECT 2214.720 10.640 2216.320 3487.280 ;
    END
    PORT
      LAYER met4 ;
        RECT 2254.720 10.640 2256.320 3487.280 ;
    END
    PORT
      LAYER met4 ;
        RECT 2294.720 10.640 2296.320 3487.280 ;
    END
    PORT
      LAYER met4 ;
        RECT 2334.720 10.640 2336.320 3487.280 ;
    END
    PORT
      LAYER met4 ;
        RECT 2374.720 10.640 2376.320 3487.280 ;
    END
    PORT
      LAYER met4 ;
        RECT 2414.720 10.640 2416.320 3487.280 ;
    END
    PORT
      LAYER met4 ;
        RECT 2454.720 10.640 2456.320 3487.280 ;
    END
    PORT
      LAYER met4 ;
        RECT 2494.720 10.640 2496.320 3487.280 ;
    END
    PORT
      LAYER met4 ;
        RECT 2534.720 10.640 2536.320 3487.280 ;
    END
    PORT
      LAYER met4 ;
        RECT 2574.720 10.640 2576.320 3487.280 ;
    END
    PORT
      LAYER met4 ;
        RECT 2614.720 10.640 2616.320 3487.280 ;
    END
    PORT
      LAYER met4 ;
        RECT 2654.720 10.640 2656.320 3487.280 ;
    END
    PORT
      LAYER met4 ;
        RECT 2694.720 10.640 2696.320 3487.280 ;
    END
    PORT
      LAYER met4 ;
        RECT 2734.720 10.640 2736.320 3487.280 ;
    END
    PORT
      LAYER met4 ;
        RECT 2774.720 10.640 2776.320 3487.280 ;
    END
    PORT
      LAYER met4 ;
        RECT 2814.720 10.640 2816.320 3487.280 ;
    END
    PORT
      LAYER met4 ;
        RECT 2854.720 10.640 2856.320 3487.280 ;
    END
    PORT
      LAYER met4 ;
        RECT 2894.720 10.640 2896.320 3487.280 ;
    END
    PORT
      LAYER met4 ;
        RECT 2934.720 10.640 2936.320 3487.280 ;
    END
    PORT
      LAYER met4 ;
        RECT 2974.720 10.640 2976.320 3487.280 ;
    END
    PORT
      LAYER met4 ;
        RECT 3014.720 10.640 3016.320 3487.280 ;
    END
    PORT
      LAYER met4 ;
        RECT 3054.720 10.640 3056.320 3487.280 ;
    END
    PORT
      LAYER met4 ;
        RECT 3094.720 10.640 3096.320 3487.280 ;
    END
    PORT
      LAYER met4 ;
        RECT 3134.720 10.640 3136.320 3487.280 ;
    END
    PORT
      LAYER met4 ;
        RECT 3174.720 10.640 3176.320 3487.280 ;
    END
    PORT
      LAYER met4 ;
        RECT 3214.720 10.640 3216.320 3487.280 ;
    END
    PORT
      LAYER met4 ;
        RECT 3254.720 10.640 3256.320 3487.280 ;
    END
    PORT
      LAYER met4 ;
        RECT 3294.720 10.640 3296.320 3487.280 ;
    END
    PORT
      LAYER met4 ;
        RECT 3334.720 10.640 3336.320 3487.280 ;
    END
    PORT
      LAYER met4 ;
        RECT 3374.720 10.640 3376.320 3487.280 ;
    END
    PORT
      LAYER met4 ;
        RECT 3414.720 10.640 3416.320 3487.280 ;
    END
    PORT
      LAYER met4 ;
        RECT 3454.720 10.640 3456.320 3487.280 ;
    END
    PORT
      LAYER met5 ;
        RECT 5.280 20.080 3494.400 21.680 ;
    END
    PORT
      LAYER met5 ;
        RECT 5.280 60.080 3494.400 61.680 ;
    END
    PORT
      LAYER met5 ;
        RECT 5.280 100.080 3494.400 101.680 ;
    END
    PORT
      LAYER met5 ;
        RECT 5.280 140.080 3494.400 141.680 ;
    END
    PORT
      LAYER met5 ;
        RECT 5.280 180.080 3494.400 181.680 ;
    END
    PORT
      LAYER met5 ;
        RECT 5.280 220.080 3494.400 221.680 ;
    END
    PORT
      LAYER met5 ;
        RECT 5.280 260.080 3494.400 261.680 ;
    END
    PORT
      LAYER met5 ;
        RECT 5.280 300.080 3494.400 301.680 ;
    END
    PORT
      LAYER met5 ;
        RECT 5.280 340.080 3494.400 341.680 ;
    END
    PORT
      LAYER met5 ;
        RECT 5.280 380.080 3494.400 381.680 ;
    END
    PORT
      LAYER met5 ;
        RECT 5.280 420.080 3494.400 421.680 ;
    END
    PORT
      LAYER met5 ;
        RECT 5.280 460.080 3494.400 461.680 ;
    END
    PORT
      LAYER met5 ;
        RECT 5.280 500.080 3494.400 501.680 ;
    END
    PORT
      LAYER met5 ;
        RECT 5.280 540.080 3494.400 541.680 ;
    END
    PORT
      LAYER met5 ;
        RECT 5.280 580.080 3494.400 581.680 ;
    END
    PORT
      LAYER met5 ;
        RECT 5.280 620.080 3494.400 621.680 ;
    END
    PORT
      LAYER met5 ;
        RECT 5.280 660.080 3494.400 661.680 ;
    END
    PORT
      LAYER met5 ;
        RECT 5.280 700.080 3494.400 701.680 ;
    END
    PORT
      LAYER met5 ;
        RECT 5.280 740.080 3494.400 741.680 ;
    END
    PORT
      LAYER met5 ;
        RECT 5.280 780.080 3494.400 781.680 ;
    END
    PORT
      LAYER met5 ;
        RECT 5.280 820.080 3494.400 821.680 ;
    END
    PORT
      LAYER met5 ;
        RECT 5.280 860.080 3494.400 861.680 ;
    END
    PORT
      LAYER met5 ;
        RECT 5.280 900.080 3494.400 901.680 ;
    END
    PORT
      LAYER met5 ;
        RECT 5.280 940.080 3494.400 941.680 ;
    END
    PORT
      LAYER met5 ;
        RECT 5.280 980.080 3494.400 981.680 ;
    END
    PORT
      LAYER met5 ;
        RECT 5.280 1020.080 3494.400 1021.680 ;
    END
    PORT
      LAYER met5 ;
        RECT 5.280 1060.080 3494.400 1061.680 ;
    END
    PORT
      LAYER met5 ;
        RECT 5.280 1100.080 3494.400 1101.680 ;
    END
    PORT
      LAYER met5 ;
        RECT 5.280 1140.080 3494.400 1141.680 ;
    END
    PORT
      LAYER met5 ;
        RECT 5.280 1180.080 3494.400 1181.680 ;
    END
    PORT
      LAYER met5 ;
        RECT 5.280 1220.080 3494.400 1221.680 ;
    END
    PORT
      LAYER met5 ;
        RECT 5.280 1260.080 3494.400 1261.680 ;
    END
    PORT
      LAYER met5 ;
        RECT 5.280 1300.080 3494.400 1301.680 ;
    END
    PORT
      LAYER met5 ;
        RECT 5.280 1340.080 3494.400 1341.680 ;
    END
    PORT
      LAYER met5 ;
        RECT 5.280 1380.080 3494.400 1381.680 ;
    END
    PORT
      LAYER met5 ;
        RECT 5.280 1420.080 3494.400 1421.680 ;
    END
    PORT
      LAYER met5 ;
        RECT 5.280 1460.080 3494.400 1461.680 ;
    END
    PORT
      LAYER met5 ;
        RECT 5.280 1500.080 3494.400 1501.680 ;
    END
    PORT
      LAYER met5 ;
        RECT 5.280 1540.080 3494.400 1541.680 ;
    END
    PORT
      LAYER met5 ;
        RECT 5.280 1580.080 3494.400 1581.680 ;
    END
    PORT
      LAYER met5 ;
        RECT 5.280 1620.080 3494.400 1621.680 ;
    END
    PORT
      LAYER met5 ;
        RECT 5.280 1660.080 3494.400 1661.680 ;
    END
    PORT
      LAYER met5 ;
        RECT 5.280 1700.080 3494.400 1701.680 ;
    END
    PORT
      LAYER met5 ;
        RECT 5.280 1740.080 3494.400 1741.680 ;
    END
    PORT
      LAYER met5 ;
        RECT 5.280 1780.080 3494.400 1781.680 ;
    END
    PORT
      LAYER met5 ;
        RECT 5.280 1820.080 3494.400 1821.680 ;
    END
    PORT
      LAYER met5 ;
        RECT 5.280 1860.080 3494.400 1861.680 ;
    END
    PORT
      LAYER met5 ;
        RECT 5.280 1900.080 3494.400 1901.680 ;
    END
    PORT
      LAYER met5 ;
        RECT 5.280 1940.080 3494.400 1941.680 ;
    END
    PORT
      LAYER met5 ;
        RECT 5.280 1980.080 3494.400 1981.680 ;
    END
    PORT
      LAYER met5 ;
        RECT 5.280 2020.080 3494.400 2021.680 ;
    END
    PORT
      LAYER met5 ;
        RECT 5.280 2060.080 3494.400 2061.680 ;
    END
    PORT
      LAYER met5 ;
        RECT 5.280 2100.080 3494.400 2101.680 ;
    END
    PORT
      LAYER met5 ;
        RECT 5.280 2140.080 3494.400 2141.680 ;
    END
    PORT
      LAYER met5 ;
        RECT 5.280 2180.080 3494.400 2181.680 ;
    END
    PORT
      LAYER met5 ;
        RECT 5.280 2220.080 3494.400 2221.680 ;
    END
    PORT
      LAYER met5 ;
        RECT 5.280 2260.080 3494.400 2261.680 ;
    END
    PORT
      LAYER met5 ;
        RECT 5.280 2300.080 3494.400 2301.680 ;
    END
    PORT
      LAYER met5 ;
        RECT 5.280 2340.080 3494.400 2341.680 ;
    END
    PORT
      LAYER met5 ;
        RECT 5.280 2380.080 3494.400 2381.680 ;
    END
    PORT
      LAYER met5 ;
        RECT 5.280 2420.080 3494.400 2421.680 ;
    END
    PORT
      LAYER met5 ;
        RECT 5.280 2460.080 3494.400 2461.680 ;
    END
    PORT
      LAYER met5 ;
        RECT 5.280 2500.080 3494.400 2501.680 ;
    END
    PORT
      LAYER met5 ;
        RECT 5.280 2540.080 3494.400 2541.680 ;
    END
    PORT
      LAYER met5 ;
        RECT 5.280 2580.080 3494.400 2581.680 ;
    END
    PORT
      LAYER met5 ;
        RECT 5.280 2620.080 3494.400 2621.680 ;
    END
    PORT
      LAYER met5 ;
        RECT 5.280 2660.080 3494.400 2661.680 ;
    END
    PORT
      LAYER met5 ;
        RECT 5.280 2700.080 3494.400 2701.680 ;
    END
    PORT
      LAYER met5 ;
        RECT 5.280 2740.080 3494.400 2741.680 ;
    END
    PORT
      LAYER met5 ;
        RECT 5.280 2780.080 3494.400 2781.680 ;
    END
    PORT
      LAYER met5 ;
        RECT 5.280 2820.080 3494.400 2821.680 ;
    END
    PORT
      LAYER met5 ;
        RECT 5.280 2860.080 3494.400 2861.680 ;
    END
    PORT
      LAYER met5 ;
        RECT 5.280 2900.080 3494.400 2901.680 ;
    END
    PORT
      LAYER met5 ;
        RECT 5.280 2940.080 3494.400 2941.680 ;
    END
    PORT
      LAYER met5 ;
        RECT 5.280 2980.080 3494.400 2981.680 ;
    END
    PORT
      LAYER met5 ;
        RECT 5.280 3020.080 3494.400 3021.680 ;
    END
    PORT
      LAYER met5 ;
        RECT 5.280 3060.080 3494.400 3061.680 ;
    END
    PORT
      LAYER met5 ;
        RECT 5.280 3100.080 3494.400 3101.680 ;
    END
    PORT
      LAYER met5 ;
        RECT 5.280 3140.080 3494.400 3141.680 ;
    END
    PORT
      LAYER met5 ;
        RECT 5.280 3180.080 3494.400 3181.680 ;
    END
    PORT
      LAYER met5 ;
        RECT 5.280 3220.080 3494.400 3221.680 ;
    END
    PORT
      LAYER met5 ;
        RECT 5.280 3260.080 3494.400 3261.680 ;
    END
    PORT
      LAYER met5 ;
        RECT 5.280 3300.080 3494.400 3301.680 ;
    END
    PORT
      LAYER met5 ;
        RECT 5.280 3340.080 3494.400 3341.680 ;
    END
    PORT
      LAYER met5 ;
        RECT 5.280 3380.080 3494.400 3381.680 ;
    END
    PORT
      LAYER met5 ;
        RECT 5.280 3420.080 3494.400 3421.680 ;
    END
    PORT
      LAYER met5 ;
        RECT 5.280 3460.080 3494.400 3461.680 ;
    END
  END VPWR
  PIN WD3[0]
    DIRECTION INPUT ;
    USE SIGNAL ;
    ANTENNAGATEAREA 0.852000 ;
    PORT
      LAYER met3 ;
        RECT 0.000 3439.480 4.000 3440.080 ;
    END
  END WD3[0]
  PIN WD3[10]
    DIRECTION INPUT ;
    USE SIGNAL ;
    ANTENNAGATEAREA 0.990000 ;
    PORT
      LAYER met3 ;
        RECT 0.000 2473.880 4.000 2474.480 ;
    END
  END WD3[10]
  PIN WD3[11]
    DIRECTION INPUT ;
    USE SIGNAL ;
    ANTENNAGATEAREA 0.990000 ;
    PORT
      LAYER met3 ;
        RECT 0.000 2377.320 4.000 2377.920 ;
    END
  END WD3[11]
  PIN WD3[12]
    DIRECTION INPUT ;
    USE SIGNAL ;
    ANTENNAGATEAREA 0.495000 ;
    PORT
      LAYER met3 ;
        RECT 0.000 2280.760 4.000 2281.360 ;
    END
  END WD3[12]
  PIN WD3[13]
    DIRECTION INPUT ;
    USE SIGNAL ;
    ANTENNAGATEAREA 0.852000 ;
    PORT
      LAYER met3 ;
        RECT 0.000 2184.200 4.000 2184.800 ;
    END
  END WD3[13]
  PIN WD3[14]
    DIRECTION INPUT ;
    USE SIGNAL ;
    ANTENNAGATEAREA 0.852000 ;
    PORT
      LAYER met3 ;
        RECT 0.000 2087.640 4.000 2088.240 ;
    END
  END WD3[14]
  PIN WD3[15]
    DIRECTION INPUT ;
    USE SIGNAL ;
    ANTENNAGATEAREA 0.742500 ;
    PORT
      LAYER met3 ;
        RECT 0.000 1991.080 4.000 1991.680 ;
    END
  END WD3[15]
  PIN WD3[16]
    DIRECTION INPUT ;
    USE SIGNAL ;
    ANTENNAGATEAREA 0.990000 ;
    PORT
      LAYER met3 ;
        RECT 0.000 1894.520 4.000 1895.120 ;
    END
  END WD3[16]
  PIN WD3[17]
    DIRECTION INPUT ;
    USE SIGNAL ;
    ANTENNAGATEAREA 0.852000 ;
    PORT
      LAYER met3 ;
        RECT 0.000 1797.960 4.000 1798.560 ;
    END
  END WD3[17]
  PIN WD3[18]
    DIRECTION INPUT ;
    USE SIGNAL ;
    ANTENNAGATEAREA 0.852000 ;
    PORT
      LAYER met3 ;
        RECT 0.000 1701.400 4.000 1702.000 ;
    END
  END WD3[18]
  PIN WD3[19]
    DIRECTION INPUT ;
    USE SIGNAL ;
    ANTENNAGATEAREA 0.852000 ;
    PORT
      LAYER met3 ;
        RECT 0.000 1604.840 4.000 1605.440 ;
    END
  END WD3[19]
  PIN WD3[1]
    DIRECTION INPUT ;
    USE SIGNAL ;
    ANTENNAGATEAREA 0.990000 ;
    PORT
      LAYER met3 ;
        RECT 0.000 3342.920 4.000 3343.520 ;
    END
  END WD3[1]
  PIN WD3[20]
    DIRECTION INPUT ;
    USE SIGNAL ;
    ANTENNAGATEAREA 0.990000 ;
    PORT
      LAYER met3 ;
        RECT 0.000 1508.280 4.000 1508.880 ;
    END
  END WD3[20]
  PIN WD3[21]
    DIRECTION INPUT ;
    USE SIGNAL ;
    ANTENNAGATEAREA 0.852000 ;
    PORT
      LAYER met3 ;
        RECT 0.000 1411.720 4.000 1412.320 ;
    END
  END WD3[21]
  PIN WD3[22]
    DIRECTION INPUT ;
    USE SIGNAL ;
    ANTENNAGATEAREA 0.990000 ;
    PORT
      LAYER met3 ;
        RECT 0.000 1315.160 4.000 1315.760 ;
    END
  END WD3[22]
  PIN WD3[23]
    DIRECTION INPUT ;
    USE SIGNAL ;
    ANTENNAGATEAREA 0.990000 ;
    PORT
      LAYER met3 ;
        RECT 0.000 1218.600 4.000 1219.200 ;
    END
  END WD3[23]
  PIN WD3[24]
    DIRECTION INPUT ;
    USE SIGNAL ;
    ANTENNAGATEAREA 0.852000 ;
    PORT
      LAYER met3 ;
        RECT 0.000 1122.040 4.000 1122.640 ;
    END
  END WD3[24]
  PIN WD3[25]
    DIRECTION INPUT ;
    USE SIGNAL ;
    ANTENNAGATEAREA 0.990000 ;
    PORT
      LAYER met3 ;
        RECT 0.000 1025.480 4.000 1026.080 ;
    END
  END WD3[25]
  PIN WD3[26]
    DIRECTION INPUT ;
    USE SIGNAL ;
    ANTENNAGATEAREA 0.990000 ;
    PORT
      LAYER met3 ;
        RECT 0.000 928.920 4.000 929.520 ;
    END
  END WD3[26]
  PIN WD3[27]
    DIRECTION INPUT ;
    USE SIGNAL ;
    ANTENNAGATEAREA 0.990000 ;
    PORT
      LAYER met3 ;
        RECT 0.000 832.360 4.000 832.960 ;
    END
  END WD3[27]
  PIN WD3[28]
    DIRECTION INPUT ;
    USE SIGNAL ;
    ANTENNAGATEAREA 0.852000 ;
    PORT
      LAYER met3 ;
        RECT 0.000 735.800 4.000 736.400 ;
    END
  END WD3[28]
  PIN WD3[29]
    DIRECTION INPUT ;
    USE SIGNAL ;
    ANTENNAGATEAREA 0.426000 ;
    PORT
      LAYER met3 ;
        RECT 0.000 639.240 4.000 639.840 ;
    END
  END WD3[29]
  PIN WD3[2]
    DIRECTION INPUT ;
    USE SIGNAL ;
    ANTENNAGATEAREA 0.495000 ;
    PORT
      LAYER met3 ;
        RECT 0.000 3246.360 4.000 3246.960 ;
    END
  END WD3[2]
  PIN WD3[30]
    DIRECTION INPUT ;
    USE SIGNAL ;
    ANTENNAGATEAREA 0.495000 ;
    PORT
      LAYER met3 ;
        RECT 0.000 542.680 4.000 543.280 ;
    END
  END WD3[30]
  PIN WD3[31]
    DIRECTION INPUT ;
    USE SIGNAL ;
    ANTENNAGATEAREA 0.247500 ;
    PORT
      LAYER met3 ;
        RECT 0.000 446.120 4.000 446.720 ;
    END
  END WD3[31]
  PIN WD3[3]
    DIRECTION INPUT ;
    USE SIGNAL ;
    ANTENNAGATEAREA 0.742500 ;
    PORT
      LAYER met3 ;
        RECT 0.000 3149.800 4.000 3150.400 ;
    END
  END WD3[3]
  PIN WD3[4]
    DIRECTION INPUT ;
    USE SIGNAL ;
    ANTENNAGATEAREA 0.426000 ;
    PORT
      LAYER met3 ;
        RECT 0.000 3053.240 4.000 3053.840 ;
    END
  END WD3[4]
  PIN WD3[5]
    DIRECTION INPUT ;
    USE SIGNAL ;
    ANTENNAGATEAREA 0.990000 ;
    PORT
      LAYER met3 ;
        RECT 0.000 2956.680 4.000 2957.280 ;
    END
  END WD3[5]
  PIN WD3[6]
    DIRECTION INPUT ;
    USE SIGNAL ;
    ANTENNAGATEAREA 0.426000 ;
    PORT
      LAYER met3 ;
        RECT 0.000 2860.120 4.000 2860.720 ;
    END
  END WD3[6]
  PIN WD3[7]
    DIRECTION INPUT ;
    USE SIGNAL ;
    ANTENNAGATEAREA 0.990000 ;
    PORT
      LAYER met3 ;
        RECT 0.000 2763.560 4.000 2764.160 ;
    END
  END WD3[7]
  PIN WD3[8]
    DIRECTION INPUT ;
    USE SIGNAL ;
    ANTENNAGATEAREA 0.990000 ;
    PORT
      LAYER met3 ;
        RECT 0.000 2667.000 4.000 2667.600 ;
    END
  END WD3[8]
  PIN WD3[9]
    DIRECTION INPUT ;
    USE SIGNAL ;
    ANTENNAGATEAREA 0.990000 ;
    PORT
      LAYER met3 ;
        RECT 0.000 2570.440 4.000 2571.040 ;
    END
  END WD3[9]
  PIN WE3
    DIRECTION INPUT ;
    USE SIGNAL ;
    ANTENNAGATEAREA 0.990000 ;
    PORT
      LAYER met3 ;
        RECT 0.000 156.440 4.000 157.040 ;
    END
  END WE3
  PIN alu_opcode[0]
    DIRECTION INPUT ;
    USE SIGNAL ;
    ANTENNAGATEAREA 0.990000 ;
    PORT
      LAYER met3 ;
        RECT 0.000 349.560 4.000 350.160 ;
    END
  END alu_opcode[0]
  PIN alu_opcode[1]
    DIRECTION INPUT ;
    USE SIGNAL ;
    ANTENNAGATEAREA 0.990000 ;
    PORT
      LAYER met3 ;
        RECT 0.000 253.000 4.000 253.600 ;
    END
  END alu_opcode[1]
  PIN alu_result[0]
    DIRECTION OUTPUT ;
    USE SIGNAL ;
    ANTENNADIFFAREA 0.340600 ;
    PORT
      LAYER met2 ;
        RECT 3439.510 0.000 3439.790 4.000 ;
    END
  END alu_result[0]
  PIN alu_result[10]
    DIRECTION OUTPUT ;
    USE SIGNAL ;
    ANTENNADIFFAREA 0.340600 ;
    PORT
      LAYER met2 ;
        RECT 2349.310 0.000 2349.590 4.000 ;
    END
  END alu_result[10]
  PIN alu_result[11]
    DIRECTION OUTPUT ;
    USE SIGNAL ;
    ANTENNADIFFAREA 0.340600 ;
    PORT
      LAYER met2 ;
        RECT 2240.290 0.000 2240.570 4.000 ;
    END
  END alu_result[11]
  PIN alu_result[12]
    DIRECTION OUTPUT ;
    USE SIGNAL ;
    ANTENNADIFFAREA 0.340600 ;
    PORT
      LAYER met2 ;
        RECT 2131.270 0.000 2131.550 4.000 ;
    END
  END alu_result[12]
  PIN alu_result[13]
    DIRECTION OUTPUT ;
    USE SIGNAL ;
    ANTENNADIFFAREA 0.340600 ;
    PORT
      LAYER met2 ;
        RECT 2022.250 0.000 2022.530 4.000 ;
    END
  END alu_result[13]
  PIN alu_result[14]
    DIRECTION OUTPUT ;
    USE SIGNAL ;
    ANTENNADIFFAREA 0.340600 ;
    PORT
      LAYER met2 ;
        RECT 1913.230 0.000 1913.510 4.000 ;
    END
  END alu_result[14]
  PIN alu_result[15]
    DIRECTION OUTPUT ;
    USE SIGNAL ;
    ANTENNADIFFAREA 0.340600 ;
    PORT
      LAYER met2 ;
        RECT 1804.210 0.000 1804.490 4.000 ;
    END
  END alu_result[15]
  PIN alu_result[16]
    DIRECTION OUTPUT ;
    USE SIGNAL ;
    ANTENNADIFFAREA 0.340600 ;
    PORT
      LAYER met2 ;
        RECT 1695.190 0.000 1695.470 4.000 ;
    END
  END alu_result[16]
  PIN alu_result[17]
    DIRECTION OUTPUT ;
    USE SIGNAL ;
    ANTENNADIFFAREA 0.340600 ;
    PORT
      LAYER met2 ;
        RECT 1586.170 0.000 1586.450 4.000 ;
    END
  END alu_result[17]
  PIN alu_result[18]
    DIRECTION OUTPUT ;
    USE SIGNAL ;
    ANTENNADIFFAREA 0.340600 ;
    PORT
      LAYER met2 ;
        RECT 1477.150 0.000 1477.430 4.000 ;
    END
  END alu_result[18]
  PIN alu_result[19]
    DIRECTION OUTPUT ;
    USE SIGNAL ;
    ANTENNADIFFAREA 0.340600 ;
    PORT
      LAYER met2 ;
        RECT 1368.130 0.000 1368.410 4.000 ;
    END
  END alu_result[19]
  PIN alu_result[1]
    DIRECTION OUTPUT ;
    USE SIGNAL ;
    ANTENNADIFFAREA 0.340600 ;
    PORT
      LAYER met2 ;
        RECT 3330.490 0.000 3330.770 4.000 ;
    END
  END alu_result[1]
  PIN alu_result[20]
    DIRECTION OUTPUT ;
    USE SIGNAL ;
    ANTENNADIFFAREA 0.340600 ;
    PORT
      LAYER met2 ;
        RECT 1259.110 0.000 1259.390 4.000 ;
    END
  END alu_result[20]
  PIN alu_result[21]
    DIRECTION OUTPUT ;
    USE SIGNAL ;
    ANTENNADIFFAREA 0.340600 ;
    PORT
      LAYER met2 ;
        RECT 1150.090 0.000 1150.370 4.000 ;
    END
  END alu_result[21]
  PIN alu_result[22]
    DIRECTION OUTPUT ;
    USE SIGNAL ;
    ANTENNADIFFAREA 0.340600 ;
    PORT
      LAYER met2 ;
        RECT 1041.070 0.000 1041.350 4.000 ;
    END
  END alu_result[22]
  PIN alu_result[23]
    DIRECTION OUTPUT ;
    USE SIGNAL ;
    ANTENNADIFFAREA 0.340600 ;
    PORT
      LAYER met2 ;
        RECT 932.050 0.000 932.330 4.000 ;
    END
  END alu_result[23]
  PIN alu_result[24]
    DIRECTION OUTPUT ;
    USE SIGNAL ;
    ANTENNADIFFAREA 0.340600 ;
    PORT
      LAYER met2 ;
        RECT 823.030 0.000 823.310 4.000 ;
    END
  END alu_result[24]
  PIN alu_result[25]
    DIRECTION OUTPUT ;
    USE SIGNAL ;
    ANTENNADIFFAREA 0.340600 ;
    PORT
      LAYER met2 ;
        RECT 714.010 0.000 714.290 4.000 ;
    END
  END alu_result[25]
  PIN alu_result[26]
    DIRECTION OUTPUT ;
    USE SIGNAL ;
    ANTENNADIFFAREA 0.340600 ;
    PORT
      LAYER met2 ;
        RECT 604.990 0.000 605.270 4.000 ;
    END
  END alu_result[26]
  PIN alu_result[27]
    DIRECTION OUTPUT ;
    USE SIGNAL ;
    ANTENNADIFFAREA 0.340600 ;
    PORT
      LAYER met2 ;
        RECT 495.970 0.000 496.250 4.000 ;
    END
  END alu_result[27]
  PIN alu_result[28]
    DIRECTION OUTPUT ;
    USE SIGNAL ;
    ANTENNADIFFAREA 0.340600 ;
    PORT
      LAYER met2 ;
        RECT 386.950 0.000 387.230 4.000 ;
    END
  END alu_result[28]
  PIN alu_result[29]
    DIRECTION OUTPUT ;
    USE SIGNAL ;
    ANTENNADIFFAREA 0.340600 ;
    PORT
      LAYER met2 ;
        RECT 277.930 0.000 278.210 4.000 ;
    END
  END alu_result[29]
  PIN alu_result[2]
    DIRECTION OUTPUT ;
    USE SIGNAL ;
    ANTENNADIFFAREA 0.340600 ;
    PORT
      LAYER met2 ;
        RECT 3221.470 0.000 3221.750 4.000 ;
    END
  END alu_result[2]
  PIN alu_result[30]
    DIRECTION OUTPUT ;
    USE SIGNAL ;
    ANTENNADIFFAREA 0.340600 ;
    PORT
      LAYER met2 ;
        RECT 168.910 0.000 169.190 4.000 ;
    END
  END alu_result[30]
  PIN alu_result[31]
    DIRECTION OUTPUT ;
    USE SIGNAL ;
    ANTENNADIFFAREA 0.340600 ;
    PORT
      LAYER met2 ;
        RECT 59.890 0.000 60.170 4.000 ;
    END
  END alu_result[31]
  PIN alu_result[3]
    DIRECTION OUTPUT ;
    USE SIGNAL ;
    ANTENNADIFFAREA 0.340600 ;
    PORT
      LAYER met2 ;
        RECT 3112.450 0.000 3112.730 4.000 ;
    END
  END alu_result[3]
  PIN alu_result[4]
    DIRECTION OUTPUT ;
    USE SIGNAL ;
    ANTENNADIFFAREA 0.340600 ;
    PORT
      LAYER met2 ;
        RECT 3003.430 0.000 3003.710 4.000 ;
    END
  END alu_result[4]
  PIN alu_result[5]
    DIRECTION OUTPUT ;
    USE SIGNAL ;
    ANTENNADIFFAREA 0.340600 ;
    PORT
      LAYER met2 ;
        RECT 2894.410 0.000 2894.690 4.000 ;
    END
  END alu_result[5]
  PIN alu_result[6]
    DIRECTION OUTPUT ;
    USE SIGNAL ;
    ANTENNADIFFAREA 0.340600 ;
    PORT
      LAYER met2 ;
        RECT 2785.390 0.000 2785.670 4.000 ;
    END
  END alu_result[6]
  PIN alu_result[7]
    DIRECTION OUTPUT ;
    USE SIGNAL ;
    ANTENNADIFFAREA 0.340600 ;
    PORT
      LAYER met2 ;
        RECT 2676.370 0.000 2676.650 4.000 ;
    END
  END alu_result[7]
  PIN alu_result[8]
    DIRECTION OUTPUT ;
    USE SIGNAL ;
    ANTENNADIFFAREA 0.340600 ;
    PORT
      LAYER met2 ;
        RECT 2567.350 0.000 2567.630 4.000 ;
    END
  END alu_result[8]
  PIN alu_result[9]
    DIRECTION OUTPUT ;
    USE SIGNAL ;
    ANTENNADIFFAREA 0.340600 ;
    PORT
      LAYER met2 ;
        RECT 2458.330 0.000 2458.610 4.000 ;
    END
  END alu_result[9]
  OBS
      LAYER nwell ;
        RECT 5.330 10.795 3494.350 3487.125 ;
      LAYER li1 ;
        RECT 5.520 10.795 3494.160 3487.125 ;
      LAYER met1 ;
        RECT 4.210 9.220 3495.010 3487.280 ;
      LAYER met2 ;
        RECT 4.230 3495.720 291.450 3496.290 ;
        RECT 292.290 3495.720 874.730 3496.290 ;
        RECT 875.570 3495.720 1458.010 3496.290 ;
        RECT 1458.850 3495.720 2041.290 3496.290 ;
        RECT 2042.130 3495.720 2624.570 3496.290 ;
        RECT 2625.410 3495.720 3207.850 3496.290 ;
        RECT 3208.690 3495.720 3494.980 3496.290 ;
        RECT 4.230 4.280 3494.980 3495.720 ;
        RECT 4.230 4.000 59.610 4.280 ;
        RECT 60.450 4.000 168.630 4.280 ;
        RECT 169.470 4.000 277.650 4.280 ;
        RECT 278.490 4.000 386.670 4.280 ;
        RECT 387.510 4.000 495.690 4.280 ;
        RECT 496.530 4.000 604.710 4.280 ;
        RECT 605.550 4.000 713.730 4.280 ;
        RECT 714.570 4.000 822.750 4.280 ;
        RECT 823.590 4.000 931.770 4.280 ;
        RECT 932.610 4.000 1040.790 4.280 ;
        RECT 1041.630 4.000 1149.810 4.280 ;
        RECT 1150.650 4.000 1258.830 4.280 ;
        RECT 1259.670 4.000 1367.850 4.280 ;
        RECT 1368.690 4.000 1476.870 4.280 ;
        RECT 1477.710 4.000 1585.890 4.280 ;
        RECT 1586.730 4.000 1694.910 4.280 ;
        RECT 1695.750 4.000 1803.930 4.280 ;
        RECT 1804.770 4.000 1912.950 4.280 ;
        RECT 1913.790 4.000 2021.970 4.280 ;
        RECT 2022.810 4.000 2130.990 4.280 ;
        RECT 2131.830 4.000 2240.010 4.280 ;
        RECT 2240.850 4.000 2349.030 4.280 ;
        RECT 2349.870 4.000 2458.050 4.280 ;
        RECT 2458.890 4.000 2567.070 4.280 ;
        RECT 2567.910 4.000 2676.090 4.280 ;
        RECT 2676.930 4.000 2785.110 4.280 ;
        RECT 2785.950 4.000 2894.130 4.280 ;
        RECT 2894.970 4.000 3003.150 4.280 ;
        RECT 3003.990 4.000 3112.170 4.280 ;
        RECT 3113.010 4.000 3221.190 4.280 ;
        RECT 3222.030 4.000 3330.210 4.280 ;
        RECT 3331.050 4.000 3439.230 4.280 ;
        RECT 3440.070 4.000 3494.980 4.280 ;
      LAYER met3 ;
        RECT 3.990 3463.600 3496.000 3487.205 ;
        RECT 3.990 3462.200 3495.600 3463.600 ;
        RECT 3.990 3440.480 3496.000 3462.200 ;
        RECT 4.400 3439.080 3496.000 3440.480 ;
        RECT 3.990 3409.200 3496.000 3439.080 ;
        RECT 3.990 3407.800 3495.600 3409.200 ;
        RECT 3.990 3354.800 3496.000 3407.800 ;
        RECT 3.990 3353.400 3495.600 3354.800 ;
        RECT 3.990 3343.920 3496.000 3353.400 ;
        RECT 4.400 3342.520 3496.000 3343.920 ;
        RECT 3.990 3300.400 3496.000 3342.520 ;
        RECT 3.990 3299.000 3495.600 3300.400 ;
        RECT 3.990 3247.360 3496.000 3299.000 ;
        RECT 4.400 3246.000 3496.000 3247.360 ;
        RECT 4.400 3245.960 3495.600 3246.000 ;
        RECT 3.990 3244.600 3495.600 3245.960 ;
        RECT 3.990 3191.600 3496.000 3244.600 ;
        RECT 3.990 3190.200 3495.600 3191.600 ;
        RECT 3.990 3150.800 3496.000 3190.200 ;
        RECT 4.400 3149.400 3496.000 3150.800 ;
        RECT 3.990 3137.200 3496.000 3149.400 ;
        RECT 3.990 3135.800 3495.600 3137.200 ;
        RECT 3.990 3082.800 3496.000 3135.800 ;
        RECT 3.990 3081.400 3495.600 3082.800 ;
        RECT 3.990 3054.240 3496.000 3081.400 ;
        RECT 4.400 3052.840 3496.000 3054.240 ;
        RECT 3.990 3028.400 3496.000 3052.840 ;
        RECT 3.990 3027.000 3495.600 3028.400 ;
        RECT 3.990 2974.000 3496.000 3027.000 ;
        RECT 3.990 2972.600 3495.600 2974.000 ;
        RECT 3.990 2957.680 3496.000 2972.600 ;
        RECT 4.400 2956.280 3496.000 2957.680 ;
        RECT 3.990 2919.600 3496.000 2956.280 ;
        RECT 3.990 2918.200 3495.600 2919.600 ;
        RECT 3.990 2865.200 3496.000 2918.200 ;
        RECT 3.990 2863.800 3495.600 2865.200 ;
        RECT 3.990 2861.120 3496.000 2863.800 ;
        RECT 4.400 2859.720 3496.000 2861.120 ;
        RECT 3.990 2810.800 3496.000 2859.720 ;
        RECT 3.990 2809.400 3495.600 2810.800 ;
        RECT 3.990 2764.560 3496.000 2809.400 ;
        RECT 4.400 2763.160 3496.000 2764.560 ;
        RECT 3.990 2756.400 3496.000 2763.160 ;
        RECT 3.990 2755.000 3495.600 2756.400 ;
        RECT 3.990 2702.000 3496.000 2755.000 ;
        RECT 3.990 2700.600 3495.600 2702.000 ;
        RECT 3.990 2668.000 3496.000 2700.600 ;
        RECT 4.400 2666.600 3496.000 2668.000 ;
        RECT 3.990 2647.600 3496.000 2666.600 ;
        RECT 3.990 2646.200 3495.600 2647.600 ;
        RECT 3.990 2593.200 3496.000 2646.200 ;
        RECT 3.990 2591.800 3495.600 2593.200 ;
        RECT 3.990 2571.440 3496.000 2591.800 ;
        RECT 4.400 2570.040 3496.000 2571.440 ;
        RECT 3.990 2538.800 3496.000 2570.040 ;
        RECT 3.990 2537.400 3495.600 2538.800 ;
        RECT 3.990 2484.400 3496.000 2537.400 ;
        RECT 3.990 2483.000 3495.600 2484.400 ;
        RECT 3.990 2474.880 3496.000 2483.000 ;
        RECT 4.400 2473.480 3496.000 2474.880 ;
        RECT 3.990 2430.000 3496.000 2473.480 ;
        RECT 3.990 2428.600 3495.600 2430.000 ;
        RECT 3.990 2378.320 3496.000 2428.600 ;
        RECT 4.400 2376.920 3496.000 2378.320 ;
        RECT 3.990 2375.600 3496.000 2376.920 ;
        RECT 3.990 2374.200 3495.600 2375.600 ;
        RECT 3.990 2321.200 3496.000 2374.200 ;
        RECT 3.990 2319.800 3495.600 2321.200 ;
        RECT 3.990 2281.760 3496.000 2319.800 ;
        RECT 4.400 2280.360 3496.000 2281.760 ;
        RECT 3.990 2266.800 3496.000 2280.360 ;
        RECT 3.990 2265.400 3495.600 2266.800 ;
        RECT 3.990 2212.400 3496.000 2265.400 ;
        RECT 3.990 2211.000 3495.600 2212.400 ;
        RECT 3.990 2185.200 3496.000 2211.000 ;
        RECT 4.400 2183.800 3496.000 2185.200 ;
        RECT 3.990 2158.000 3496.000 2183.800 ;
        RECT 3.990 2156.600 3495.600 2158.000 ;
        RECT 3.990 2103.600 3496.000 2156.600 ;
        RECT 3.990 2102.200 3495.600 2103.600 ;
        RECT 3.990 2088.640 3496.000 2102.200 ;
        RECT 4.400 2087.240 3496.000 2088.640 ;
        RECT 3.990 2049.200 3496.000 2087.240 ;
        RECT 3.990 2047.800 3495.600 2049.200 ;
        RECT 3.990 1994.800 3496.000 2047.800 ;
        RECT 3.990 1993.400 3495.600 1994.800 ;
        RECT 3.990 1992.080 3496.000 1993.400 ;
        RECT 4.400 1990.680 3496.000 1992.080 ;
        RECT 3.990 1940.400 3496.000 1990.680 ;
        RECT 3.990 1939.000 3495.600 1940.400 ;
        RECT 3.990 1895.520 3496.000 1939.000 ;
        RECT 4.400 1894.120 3496.000 1895.520 ;
        RECT 3.990 1886.000 3496.000 1894.120 ;
        RECT 3.990 1884.600 3495.600 1886.000 ;
        RECT 3.990 1831.600 3496.000 1884.600 ;
        RECT 3.990 1830.200 3495.600 1831.600 ;
        RECT 3.990 1798.960 3496.000 1830.200 ;
        RECT 4.400 1797.560 3496.000 1798.960 ;
        RECT 3.990 1777.200 3496.000 1797.560 ;
        RECT 3.990 1775.800 3495.600 1777.200 ;
        RECT 3.990 1722.800 3496.000 1775.800 ;
        RECT 3.990 1721.400 3495.600 1722.800 ;
        RECT 3.990 1702.400 3496.000 1721.400 ;
        RECT 4.400 1701.000 3496.000 1702.400 ;
        RECT 3.990 1668.400 3496.000 1701.000 ;
        RECT 3.990 1667.000 3495.600 1668.400 ;
        RECT 3.990 1614.000 3496.000 1667.000 ;
        RECT 3.990 1612.600 3495.600 1614.000 ;
        RECT 3.990 1605.840 3496.000 1612.600 ;
        RECT 4.400 1604.440 3496.000 1605.840 ;
        RECT 3.990 1559.600 3496.000 1604.440 ;
        RECT 3.990 1558.200 3495.600 1559.600 ;
        RECT 3.990 1509.280 3496.000 1558.200 ;
        RECT 4.400 1507.880 3496.000 1509.280 ;
        RECT 3.990 1505.200 3496.000 1507.880 ;
        RECT 3.990 1503.800 3495.600 1505.200 ;
        RECT 3.990 1450.800 3496.000 1503.800 ;
        RECT 3.990 1449.400 3495.600 1450.800 ;
        RECT 3.990 1412.720 3496.000 1449.400 ;
        RECT 4.400 1411.320 3496.000 1412.720 ;
        RECT 3.990 1396.400 3496.000 1411.320 ;
        RECT 3.990 1395.000 3495.600 1396.400 ;
        RECT 3.990 1342.000 3496.000 1395.000 ;
        RECT 3.990 1340.600 3495.600 1342.000 ;
        RECT 3.990 1316.160 3496.000 1340.600 ;
        RECT 4.400 1314.760 3496.000 1316.160 ;
        RECT 3.990 1287.600 3496.000 1314.760 ;
        RECT 3.990 1286.200 3495.600 1287.600 ;
        RECT 3.990 1233.200 3496.000 1286.200 ;
        RECT 3.990 1231.800 3495.600 1233.200 ;
        RECT 3.990 1219.600 3496.000 1231.800 ;
        RECT 4.400 1218.200 3496.000 1219.600 ;
        RECT 3.990 1178.800 3496.000 1218.200 ;
        RECT 3.990 1177.400 3495.600 1178.800 ;
        RECT 3.990 1124.400 3496.000 1177.400 ;
        RECT 3.990 1123.040 3495.600 1124.400 ;
        RECT 4.400 1123.000 3495.600 1123.040 ;
        RECT 4.400 1121.640 3496.000 1123.000 ;
        RECT 3.990 1070.000 3496.000 1121.640 ;
        RECT 3.990 1068.600 3495.600 1070.000 ;
        RECT 3.990 1026.480 3496.000 1068.600 ;
        RECT 4.400 1025.080 3496.000 1026.480 ;
        RECT 3.990 1015.600 3496.000 1025.080 ;
        RECT 3.990 1014.200 3495.600 1015.600 ;
        RECT 3.990 961.200 3496.000 1014.200 ;
        RECT 3.990 959.800 3495.600 961.200 ;
        RECT 3.990 929.920 3496.000 959.800 ;
        RECT 4.400 928.520 3496.000 929.920 ;
        RECT 3.990 906.800 3496.000 928.520 ;
        RECT 3.990 905.400 3495.600 906.800 ;
        RECT 3.990 852.400 3496.000 905.400 ;
        RECT 3.990 851.000 3495.600 852.400 ;
        RECT 3.990 833.360 3496.000 851.000 ;
        RECT 4.400 831.960 3496.000 833.360 ;
        RECT 3.990 798.000 3496.000 831.960 ;
        RECT 3.990 796.600 3495.600 798.000 ;
        RECT 3.990 743.600 3496.000 796.600 ;
        RECT 3.990 742.200 3495.600 743.600 ;
        RECT 3.990 736.800 3496.000 742.200 ;
        RECT 4.400 735.400 3496.000 736.800 ;
        RECT 3.990 689.200 3496.000 735.400 ;
        RECT 3.990 687.800 3495.600 689.200 ;
        RECT 3.990 640.240 3496.000 687.800 ;
        RECT 4.400 638.840 3496.000 640.240 ;
        RECT 3.990 634.800 3496.000 638.840 ;
        RECT 3.990 633.400 3495.600 634.800 ;
        RECT 3.990 580.400 3496.000 633.400 ;
        RECT 3.990 579.000 3495.600 580.400 ;
        RECT 3.990 543.680 3496.000 579.000 ;
        RECT 4.400 542.280 3496.000 543.680 ;
        RECT 3.990 526.000 3496.000 542.280 ;
        RECT 3.990 524.600 3495.600 526.000 ;
        RECT 3.990 471.600 3496.000 524.600 ;
        RECT 3.990 470.200 3495.600 471.600 ;
        RECT 3.990 447.120 3496.000 470.200 ;
        RECT 4.400 445.720 3496.000 447.120 ;
        RECT 3.990 417.200 3496.000 445.720 ;
        RECT 3.990 415.800 3495.600 417.200 ;
        RECT 3.990 362.800 3496.000 415.800 ;
        RECT 3.990 361.400 3495.600 362.800 ;
        RECT 3.990 350.560 3496.000 361.400 ;
        RECT 4.400 349.160 3496.000 350.560 ;
        RECT 3.990 308.400 3496.000 349.160 ;
        RECT 3.990 307.000 3495.600 308.400 ;
        RECT 3.990 254.000 3496.000 307.000 ;
        RECT 4.400 252.600 3495.600 254.000 ;
        RECT 3.990 199.600 3496.000 252.600 ;
        RECT 3.990 198.200 3495.600 199.600 ;
        RECT 3.990 157.440 3496.000 198.200 ;
        RECT 4.400 156.040 3496.000 157.440 ;
        RECT 3.990 145.200 3496.000 156.040 ;
        RECT 3.990 143.800 3495.600 145.200 ;
        RECT 3.990 90.800 3496.000 143.800 ;
        RECT 3.990 89.400 3495.600 90.800 ;
        RECT 3.990 60.880 3496.000 89.400 ;
        RECT 4.400 59.480 3496.000 60.880 ;
        RECT 3.990 36.400 3496.000 59.480 ;
        RECT 3.990 35.000 3495.600 36.400 ;
        RECT 3.990 10.715 3496.000 35.000 ;
      LAYER met4 ;
        RECT 436.375 60.695 454.320 2981.625 ;
        RECT 456.720 60.695 457.620 2981.625 ;
        RECT 460.020 60.695 494.320 2981.625 ;
        RECT 496.720 60.695 497.620 2981.625 ;
        RECT 500.020 60.695 534.320 2981.625 ;
        RECT 536.720 60.695 537.620 2981.625 ;
        RECT 540.020 60.695 574.320 2981.625 ;
        RECT 576.720 60.695 577.620 2981.625 ;
        RECT 580.020 60.695 614.320 2981.625 ;
        RECT 616.720 60.695 617.620 2981.625 ;
        RECT 620.020 60.695 654.320 2981.625 ;
        RECT 656.720 60.695 657.620 2981.625 ;
        RECT 660.020 60.695 694.320 2981.625 ;
        RECT 696.720 60.695 697.620 2981.625 ;
        RECT 700.020 60.695 734.320 2981.625 ;
        RECT 736.720 60.695 737.620 2981.625 ;
        RECT 740.020 60.695 774.320 2981.625 ;
        RECT 776.720 60.695 777.620 2981.625 ;
        RECT 780.020 60.695 814.320 2981.625 ;
        RECT 816.720 60.695 817.620 2981.625 ;
        RECT 820.020 60.695 854.320 2981.625 ;
        RECT 856.720 60.695 857.620 2981.625 ;
        RECT 860.020 60.695 894.320 2981.625 ;
        RECT 896.720 60.695 897.620 2981.625 ;
        RECT 900.020 60.695 934.320 2981.625 ;
        RECT 936.720 60.695 937.620 2981.625 ;
        RECT 940.020 60.695 974.320 2981.625 ;
        RECT 976.720 60.695 977.620 2981.625 ;
        RECT 980.020 60.695 1014.320 2981.625 ;
        RECT 1016.720 60.695 1017.620 2981.625 ;
        RECT 1020.020 60.695 1054.320 2981.625 ;
        RECT 1056.720 60.695 1057.620 2981.625 ;
        RECT 1060.020 60.695 1094.320 2981.625 ;
        RECT 1096.720 60.695 1097.620 2981.625 ;
        RECT 1100.020 60.695 1134.320 2981.625 ;
        RECT 1136.720 60.695 1137.620 2981.625 ;
        RECT 1140.020 60.695 1174.320 2981.625 ;
        RECT 1176.720 60.695 1177.620 2981.625 ;
        RECT 1180.020 60.695 1214.320 2981.625 ;
        RECT 1216.720 60.695 1217.620 2981.625 ;
        RECT 1220.020 60.695 1254.320 2981.625 ;
        RECT 1256.720 60.695 1257.620 2981.625 ;
        RECT 1260.020 60.695 1294.320 2981.625 ;
        RECT 1296.720 60.695 1297.620 2981.625 ;
        RECT 1300.020 60.695 1334.320 2981.625 ;
        RECT 1336.720 60.695 1337.620 2981.625 ;
        RECT 1340.020 60.695 1374.320 2981.625 ;
        RECT 1376.720 60.695 1377.620 2981.625 ;
        RECT 1380.020 60.695 1414.320 2981.625 ;
        RECT 1416.720 60.695 1417.620 2981.625 ;
        RECT 1420.020 60.695 1454.320 2981.625 ;
        RECT 1456.720 60.695 1457.620 2981.625 ;
        RECT 1460.020 60.695 1494.320 2981.625 ;
        RECT 1496.720 60.695 1497.620 2981.625 ;
        RECT 1500.020 60.695 1534.320 2981.625 ;
        RECT 1536.720 60.695 1537.620 2981.625 ;
        RECT 1540.020 60.695 1574.320 2981.625 ;
        RECT 1576.720 60.695 1577.620 2981.625 ;
        RECT 1580.020 60.695 1614.320 2981.625 ;
        RECT 1616.720 60.695 1617.620 2981.625 ;
        RECT 1620.020 60.695 1654.320 2981.625 ;
        RECT 1656.720 60.695 1657.620 2981.625 ;
        RECT 1660.020 60.695 1694.320 2981.625 ;
        RECT 1696.720 60.695 1697.620 2981.625 ;
        RECT 1700.020 60.695 1734.320 2981.625 ;
        RECT 1736.720 60.695 1737.620 2981.625 ;
        RECT 1740.020 60.695 1774.320 2981.625 ;
        RECT 1776.720 60.695 1777.620 2981.625 ;
        RECT 1780.020 60.695 1814.320 2981.625 ;
        RECT 1816.720 60.695 1817.620 2981.625 ;
        RECT 1820.020 60.695 1854.320 2981.625 ;
        RECT 1856.720 60.695 1857.620 2981.625 ;
        RECT 1860.020 60.695 1894.320 2981.625 ;
        RECT 1896.720 60.695 1897.620 2981.625 ;
        RECT 1900.020 60.695 1934.320 2981.625 ;
        RECT 1936.720 60.695 1937.620 2981.625 ;
        RECT 1940.020 60.695 1974.320 2981.625 ;
        RECT 1976.720 60.695 1977.620 2981.625 ;
        RECT 1980.020 60.695 2014.320 2981.625 ;
        RECT 2016.720 60.695 2017.620 2981.625 ;
        RECT 2020.020 60.695 2054.320 2981.625 ;
        RECT 2056.720 60.695 2057.620 2981.625 ;
        RECT 2060.020 60.695 2094.320 2981.625 ;
        RECT 2096.720 60.695 2097.620 2981.625 ;
        RECT 2100.020 60.695 2134.320 2981.625 ;
        RECT 2136.720 60.695 2137.620 2981.625 ;
        RECT 2140.020 60.695 2174.320 2981.625 ;
        RECT 2176.720 60.695 2177.620 2981.625 ;
        RECT 2180.020 60.695 2214.320 2981.625 ;
        RECT 2216.720 60.695 2217.620 2981.625 ;
        RECT 2220.020 60.695 2254.320 2981.625 ;
        RECT 2256.720 60.695 2257.620 2981.625 ;
        RECT 2260.020 60.695 2294.320 2981.625 ;
        RECT 2296.720 60.695 2297.620 2981.625 ;
        RECT 2300.020 60.695 2334.320 2981.625 ;
        RECT 2336.720 60.695 2337.620 2981.625 ;
        RECT 2340.020 60.695 2374.320 2981.625 ;
        RECT 2376.720 60.695 2377.620 2981.625 ;
        RECT 2380.020 60.695 2414.320 2981.625 ;
        RECT 2416.720 60.695 2417.620 2981.625 ;
        RECT 2420.020 60.695 2454.320 2981.625 ;
        RECT 2456.720 60.695 2457.620 2981.625 ;
        RECT 2460.020 60.695 2494.320 2981.625 ;
        RECT 2496.720 60.695 2497.620 2981.625 ;
        RECT 2500.020 60.695 2534.320 2981.625 ;
        RECT 2536.720 60.695 2537.620 2981.625 ;
        RECT 2540.020 60.695 2574.320 2981.625 ;
        RECT 2576.720 60.695 2577.620 2981.625 ;
        RECT 2580.020 60.695 2614.320 2981.625 ;
        RECT 2616.720 60.695 2617.620 2981.625 ;
        RECT 2620.020 60.695 2654.320 2981.625 ;
        RECT 2656.720 60.695 2657.620 2981.625 ;
        RECT 2660.020 60.695 2694.320 2981.625 ;
        RECT 2696.720 60.695 2697.620 2981.625 ;
        RECT 2700.020 60.695 2734.320 2981.625 ;
        RECT 2736.720 60.695 2737.620 2981.625 ;
        RECT 2740.020 60.695 2774.320 2981.625 ;
        RECT 2776.720 60.695 2777.620 2981.625 ;
        RECT 2780.020 60.695 2814.320 2981.625 ;
        RECT 2816.720 60.695 2817.620 2981.625 ;
        RECT 2820.020 60.695 2854.320 2981.625 ;
        RECT 2856.720 60.695 2857.620 2981.625 ;
        RECT 2860.020 60.695 2894.320 2981.625 ;
        RECT 2896.720 60.695 2897.620 2981.625 ;
        RECT 2900.020 60.695 2934.320 2981.625 ;
        RECT 2936.720 60.695 2937.620 2981.625 ;
        RECT 2940.020 60.695 2974.320 2981.625 ;
        RECT 2976.720 60.695 2977.620 2981.625 ;
        RECT 2980.020 60.695 3014.320 2981.625 ;
        RECT 3016.720 60.695 3017.620 2981.625 ;
        RECT 3020.020 60.695 3053.185 2981.625 ;
  END
END TopModule
END LIBRARY

